##
## LEF for PtnCells ;
## created by Innovus v15.23-s045_1 on Sat Mar 22 13:16:31 2025
##

VERSION 5.8 ;

BUSBITCHARS "[]" ;
DIVIDERCHAR "/" ;

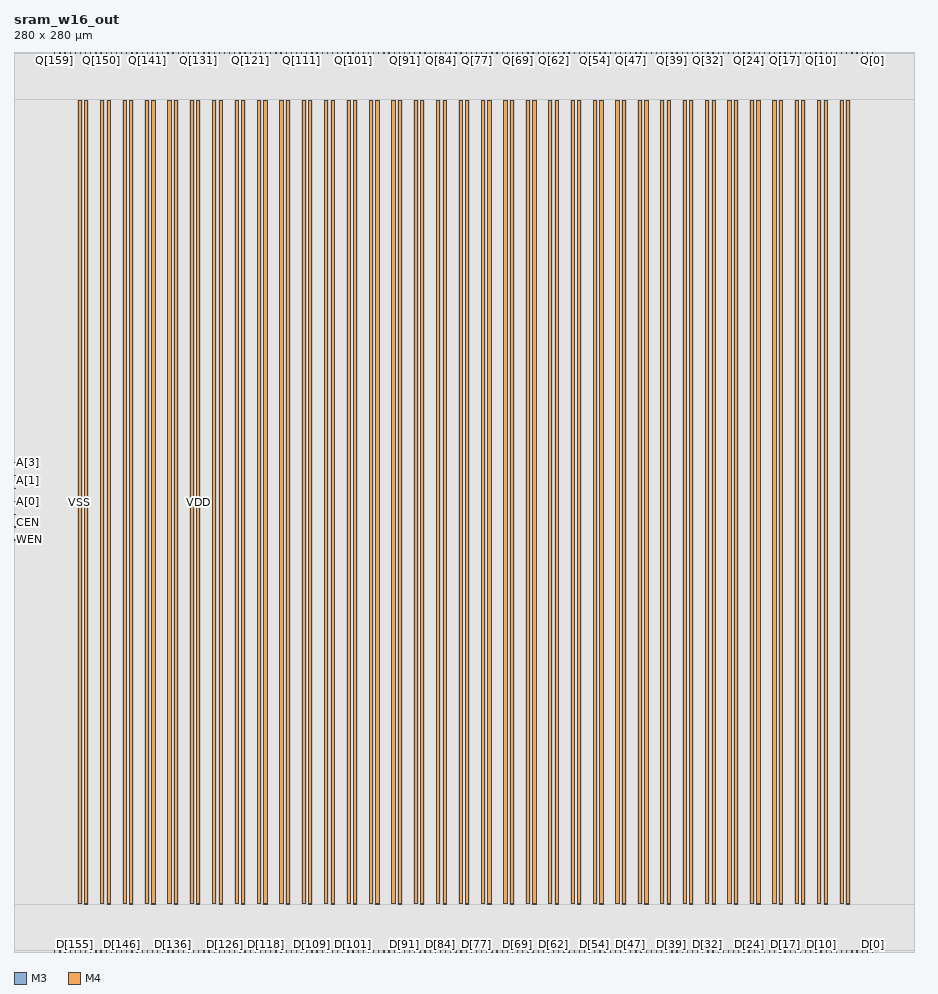
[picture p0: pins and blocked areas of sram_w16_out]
MACRO sram_w16_out
  CLASS BLOCK ;
  SIZE 280.0000 BY 280.0000 ;
  FOREIGN sram_w16_out 0.0000 0.0000 ;
  ORIGIN 0 0 ;
  SYMMETRY X Y R90 ;
  PIN clk
    DIRECTION INPUT ;
    USE SIGNAL ;
    PORT
      LAYER M3 ;
        RECT 0.0000 132.1500 0.5200 132.2500 ;
    END
  END clk
  PIN D[159]
    DIRECTION INPUT ;
    USE SIGNAL ;
    PORT
      LAYER M4 ;
        RECT 12.6500 0.0000 12.7500 0.5200 ;
    END
  END D[159]
  PIN D[158]
    DIRECTION INPUT ;
    USE SIGNAL ;
    PORT
      LAYER M4 ;
        RECT 14.2500 0.0000 14.3500 0.5200 ;
    END
  END D[158]
  PIN D[157]
    DIRECTION INPUT ;
    USE SIGNAL ;
    PORT
      LAYER M4 ;
        RECT 15.8500 0.0000 15.9500 0.5200 ;
    END
  END D[157]
  PIN D[156]
    DIRECTION INPUT ;
    USE SIGNAL ;
    PORT
      LAYER M4 ;
        RECT 17.4500 0.0000 17.5500 0.5200 ;
    END
  END D[156]
  PIN D[155]
    DIRECTION INPUT ;
    USE SIGNAL ;
    PORT
      LAYER M4 ;
        RECT 19.0500 0.0000 19.1500 0.5200 ;
    END
  END D[155]
  PIN D[154]
    DIRECTION INPUT ;
    USE SIGNAL ;
    PORT
      LAYER M4 ;
        RECT 20.6500 0.0000 20.7500 0.5200 ;
    END
  END D[154]
  PIN D[153]
    DIRECTION INPUT ;
    USE SIGNAL ;
    PORT
      LAYER M4 ;
        RECT 22.2500 0.0000 22.3500 0.5200 ;
    END
  END D[153]
  PIN D[152]
    DIRECTION INPUT ;
    USE SIGNAL ;
    PORT
      LAYER M4 ;
        RECT 23.8500 0.0000 23.9500 0.5200 ;
    END
  END D[152]
  PIN D[151]
    DIRECTION INPUT ;
    USE SIGNAL ;
    PORT
      LAYER M4 ;
        RECT 25.4500 0.0000 25.5500 0.5200 ;
    END
  END D[151]
  PIN D[150]
    DIRECTION INPUT ;
    USE SIGNAL ;
    PORT
      LAYER M4 ;
        RECT 27.0500 0.0000 27.1500 0.5200 ;
    END
  END D[150]
  PIN D[149]
    DIRECTION INPUT ;
    USE SIGNAL ;
    PORT
      LAYER M4 ;
        RECT 28.6500 0.0000 28.7500 0.5200 ;
    END
  END D[149]
  PIN D[148]
    DIRECTION INPUT ;
    USE SIGNAL ;
    PORT
      LAYER M4 ;
        RECT 30.2500 0.0000 30.3500 0.5200 ;
    END
  END D[148]
  PIN D[147]
    DIRECTION INPUT ;
    USE SIGNAL ;
    PORT
      LAYER M4 ;
        RECT 31.8500 0.0000 31.9500 0.5200 ;
    END
  END D[147]
  PIN D[146]
    DIRECTION INPUT ;
    USE SIGNAL ;
    PORT
      LAYER M4 ;
        RECT 33.4500 0.0000 33.5500 0.5200 ;
    END
  END D[146]
  PIN D[145]
    DIRECTION INPUT ;
    USE SIGNAL ;
    PORT
      LAYER M4 ;
        RECT 35.0500 0.0000 35.1500 0.5200 ;
    END
  END D[145]
  PIN D[144]
    DIRECTION INPUT ;
    USE SIGNAL ;
    PORT
      LAYER M4 ;
        RECT 36.6500 0.0000 36.7500 0.5200 ;
    END
  END D[144]
  PIN D[143]
    DIRECTION INPUT ;
    USE SIGNAL ;
    PORT
      LAYER M4 ;
        RECT 38.2500 0.0000 38.3500 0.5200 ;
    END
  END D[143]
  PIN D[142]
    DIRECTION INPUT ;
    USE SIGNAL ;
    PORT
      LAYER M4 ;
        RECT 39.8500 0.0000 39.9500 0.5200 ;
    END
  END D[142]
  PIN D[141]
    DIRECTION INPUT ;
    USE SIGNAL ;
    PORT
      LAYER M4 ;
        RECT 41.4500 0.0000 41.5500 0.5200 ;
    END
  END D[141]
  PIN D[140]
    DIRECTION INPUT ;
    USE SIGNAL ;
    PORT
      LAYER M4 ;
        RECT 43.0500 0.0000 43.1500 0.5200 ;
    END
  END D[140]
  PIN D[139]
    DIRECTION INPUT ;
    USE SIGNAL ;
    PORT
      LAYER M4 ;
        RECT 44.6500 0.0000 44.7500 0.5200 ;
    END
  END D[139]
  PIN D[138]
    DIRECTION INPUT ;
    USE SIGNAL ;
    PORT
      LAYER M4 ;
        RECT 46.2500 0.0000 46.3500 0.5200 ;
    END
  END D[138]
  PIN D[137]
    DIRECTION INPUT ;
    USE SIGNAL ;
    PORT
      LAYER M4 ;
        RECT 47.8500 0.0000 47.9500 0.5200 ;
    END
  END D[137]
  PIN D[136]
    DIRECTION INPUT ;
    USE SIGNAL ;
    PORT
      LAYER M4 ;
        RECT 49.4500 0.0000 49.5500 0.5200 ;
    END
  END D[136]
  PIN D[135]
    DIRECTION INPUT ;
    USE SIGNAL ;
    PORT
      LAYER M4 ;
        RECT 51.0500 0.0000 51.1500 0.5200 ;
    END
  END D[135]
  PIN D[134]
    DIRECTION INPUT ;
    USE SIGNAL ;
    PORT
      LAYER M4 ;
        RECT 52.6500 0.0000 52.7500 0.5200 ;
    END
  END D[134]
  PIN D[133]
    DIRECTION INPUT ;
    USE SIGNAL ;
    PORT
      LAYER M4 ;
        RECT 54.2500 0.0000 54.3500 0.5200 ;
    END
  END D[133]
  PIN D[132]
    DIRECTION INPUT ;
    USE SIGNAL ;
    PORT
      LAYER M4 ;
        RECT 55.8500 0.0000 55.9500 0.5200 ;
    END
  END D[132]
  PIN D[131]
    DIRECTION INPUT ;
    USE SIGNAL ;
    PORT
      LAYER M4 ;
        RECT 57.4500 0.0000 57.5500 0.5200 ;
    END
  END D[131]
  PIN D[130]
    DIRECTION INPUT ;
    USE SIGNAL ;
    PORT
      LAYER M4 ;
        RECT 59.0500 0.0000 59.1500 0.5200 ;
    END
  END D[130]
  PIN D[129]
    DIRECTION INPUT ;
    USE SIGNAL ;
    PORT
      LAYER M4 ;
        RECT 60.6500 0.0000 60.7500 0.5200 ;
    END
  END D[129]
  PIN D[128]
    DIRECTION INPUT ;
    USE SIGNAL ;
    PORT
      LAYER M4 ;
        RECT 62.2500 0.0000 62.3500 0.5200 ;
    END
  END D[128]
  PIN D[127]
    DIRECTION INPUT ;
    USE SIGNAL ;
    PORT
      LAYER M4 ;
        RECT 63.8500 0.0000 63.9500 0.5200 ;
    END
  END D[127]
  PIN D[126]
    DIRECTION INPUT ;
    USE SIGNAL ;
    PORT
      LAYER M4 ;
        RECT 65.4500 0.0000 65.5500 0.5200 ;
    END
  END D[126]
  PIN D[125]
    DIRECTION INPUT ;
    USE SIGNAL ;
    PORT
      LAYER M4 ;
        RECT 67.0500 0.0000 67.1500 0.5200 ;
    END
  END D[125]
  PIN D[124]
    DIRECTION INPUT ;
    USE SIGNAL ;
    PORT
      LAYER M4 ;
        RECT 68.6500 0.0000 68.7500 0.5200 ;
    END
  END D[124]
  PIN D[123]
    DIRECTION INPUT ;
    USE SIGNAL ;
    PORT
      LAYER M4 ;
        RECT 70.2500 0.0000 70.3500 0.5200 ;
    END
  END D[123]
  PIN D[122]
    DIRECTION INPUT ;
    USE SIGNAL ;
    PORT
      LAYER M4 ;
        RECT 71.8500 0.0000 71.9500 0.5200 ;
    END
  END D[122]
  PIN D[121]
    DIRECTION INPUT ;
    USE SIGNAL ;
    PORT
      LAYER M4 ;
        RECT 73.4500 0.0000 73.5500 0.5200 ;
    END
  END D[121]
  PIN D[120]
    DIRECTION INPUT ;
    USE SIGNAL ;
    PORT
      LAYER M4 ;
        RECT 75.0500 0.0000 75.1500 0.5200 ;
    END
  END D[120]
  PIN D[119]
    DIRECTION INPUT ;
    USE SIGNAL ;
    PORT
      LAYER M4 ;
        RECT 76.6500 0.0000 76.7500 0.5200 ;
    END
  END D[119]
  PIN D[118]
    DIRECTION INPUT ;
    USE SIGNAL ;
    PORT
      LAYER M4 ;
        RECT 78.2500 0.0000 78.3500 0.5200 ;
    END
  END D[118]
  PIN D[117]
    DIRECTION INPUT ;
    USE SIGNAL ;
    PORT
      LAYER M4 ;
        RECT 79.8500 0.0000 79.9500 0.5200 ;
    END
  END D[117]
  PIN D[116]
    DIRECTION INPUT ;
    USE SIGNAL ;
    PORT
      LAYER M4 ;
        RECT 81.4500 0.0000 81.5500 0.5200 ;
    END
  END D[116]
  PIN D[115]
    DIRECTION INPUT ;
    USE SIGNAL ;
    PORT
      LAYER M4 ;
        RECT 83.0500 0.0000 83.1500 0.5200 ;
    END
  END D[115]
  PIN D[114]
    DIRECTION INPUT ;
    USE SIGNAL ;
    PORT
      LAYER M4 ;
        RECT 84.6500 0.0000 84.7500 0.5200 ;
    END
  END D[114]
  PIN D[113]
    DIRECTION INPUT ;
    USE SIGNAL ;
    PORT
      LAYER M4 ;
        RECT 86.2500 0.0000 86.3500 0.5200 ;
    END
  END D[113]
  PIN D[112]
    DIRECTION INPUT ;
    USE SIGNAL ;
    PORT
      LAYER M4 ;
        RECT 87.8500 0.0000 87.9500 0.5200 ;
    END
  END D[112]
  PIN D[111]
    DIRECTION INPUT ;
    USE SIGNAL ;
    PORT
      LAYER M4 ;
        RECT 89.4500 0.0000 89.5500 0.5200 ;
    END
  END D[111]
  PIN D[110]
    DIRECTION INPUT ;
    USE SIGNAL ;
    PORT
      LAYER M4 ;
        RECT 91.0500 0.0000 91.1500 0.5200 ;
    END
  END D[110]
  PIN D[109]
    DIRECTION INPUT ;
    USE SIGNAL ;
    PORT
      LAYER M4 ;
        RECT 92.6500 0.0000 92.7500 0.5200 ;
    END
  END D[109]
  PIN D[108]
    DIRECTION INPUT ;
    USE SIGNAL ;
    PORT
      LAYER M4 ;
        RECT 94.2500 0.0000 94.3500 0.5200 ;
    END
  END D[108]
  PIN D[107]
    DIRECTION INPUT ;
    USE SIGNAL ;
    PORT
      LAYER M4 ;
        RECT 95.8500 0.0000 95.9500 0.5200 ;
    END
  END D[107]
  PIN D[106]
    DIRECTION INPUT ;
    USE SIGNAL ;
    PORT
      LAYER M4 ;
        RECT 97.4500 0.0000 97.5500 0.5200 ;
    END
  END D[106]
  PIN D[105]
    DIRECTION INPUT ;
    USE SIGNAL ;
    PORT
      LAYER M4 ;
        RECT 99.0500 0.0000 99.1500 0.5200 ;
    END
  END D[105]
  PIN D[104]
    DIRECTION INPUT ;
    USE SIGNAL ;
    PORT
      LAYER M4 ;
        RECT 100.6500 0.0000 100.7500 0.5200 ;
    END
  END D[104]
  PIN D[103]
    DIRECTION INPUT ;
    USE SIGNAL ;
    PORT
      LAYER M4 ;
        RECT 102.2500 0.0000 102.3500 0.5200 ;
    END
  END D[103]
  PIN D[102]
    DIRECTION INPUT ;
    USE SIGNAL ;
    PORT
      LAYER M4 ;
        RECT 103.8500 0.0000 103.9500 0.5200 ;
    END
  END D[102]
  PIN D[101]
    DIRECTION INPUT ;
    USE SIGNAL ;
    PORT
      LAYER M4 ;
        RECT 105.4500 0.0000 105.5500 0.5200 ;
    END
  END D[101]
  PIN D[100]
    DIRECTION INPUT ;
    USE SIGNAL ;
    PORT
      LAYER M4 ;
        RECT 107.0500 0.0000 107.1500 0.5200 ;
    END
  END D[100]
  PIN D[99]
    DIRECTION INPUT ;
    USE SIGNAL ;
    PORT
      LAYER M4 ;
        RECT 108.6500 0.0000 108.7500 0.5200 ;
    END
  END D[99]
  PIN D[98]
    DIRECTION INPUT ;
    USE SIGNAL ;
    PORT
      LAYER M4 ;
        RECT 110.2500 0.0000 110.3500 0.5200 ;
    END
  END D[98]
  PIN D[97]
    DIRECTION INPUT ;
    USE SIGNAL ;
    PORT
      LAYER M4 ;
        RECT 111.8500 0.0000 111.9500 0.5200 ;
    END
  END D[97]
  PIN D[96]
    DIRECTION INPUT ;
    USE SIGNAL ;
    PORT
      LAYER M4 ;
        RECT 113.4500 0.0000 113.5500 0.5200 ;
    END
  END D[96]
  PIN D[95]
    DIRECTION INPUT ;
    USE SIGNAL ;
    PORT
      LAYER M4 ;
        RECT 115.0500 0.0000 115.1500 0.5200 ;
    END
  END D[95]
  PIN D[94]
    DIRECTION INPUT ;
    USE SIGNAL ;
    PORT
      LAYER M4 ;
        RECT 116.6500 0.0000 116.7500 0.5200 ;
    END
  END D[94]
  PIN D[93]
    DIRECTION INPUT ;
    USE SIGNAL ;
    PORT
      LAYER M4 ;
        RECT 118.2500 0.0000 118.3500 0.5200 ;
    END
  END D[93]
  PIN D[92]
    DIRECTION INPUT ;
    USE SIGNAL ;
    PORT
      LAYER M4 ;
        RECT 119.8500 0.0000 119.9500 0.5200 ;
    END
  END D[92]
  PIN D[91]
    DIRECTION INPUT ;
    USE SIGNAL ;
    PORT
      LAYER M4 ;
        RECT 121.4500 0.0000 121.5500 0.5200 ;
    END
  END D[91]
  PIN D[90]
    DIRECTION INPUT ;
    USE SIGNAL ;
    PORT
      LAYER M4 ;
        RECT 123.0500 0.0000 123.1500 0.5200 ;
    END
  END D[90]
  PIN D[89]
    DIRECTION INPUT ;
    USE SIGNAL ;
    PORT
      LAYER M4 ;
        RECT 124.6500 0.0000 124.7500 0.5200 ;
    END
  END D[89]
  PIN D[88]
    DIRECTION INPUT ;
    USE SIGNAL ;
    PORT
      LAYER M4 ;
        RECT 126.2500 0.0000 126.3500 0.5200 ;
    END
  END D[88]
  PIN D[87]
    DIRECTION INPUT ;
    USE SIGNAL ;
    PORT
      LAYER M4 ;
        RECT 127.8500 0.0000 127.9500 0.5200 ;
    END
  END D[87]
  PIN D[86]
    DIRECTION INPUT ;
    USE SIGNAL ;
    PORT
      LAYER M4 ;
        RECT 129.4500 0.0000 129.5500 0.5200 ;
    END
  END D[86]
  PIN D[85]
    DIRECTION INPUT ;
    USE SIGNAL ;
    PORT
      LAYER M4 ;
        RECT 131.0500 0.0000 131.1500 0.5200 ;
    END
  END D[85]
  PIN D[84]
    DIRECTION INPUT ;
    USE SIGNAL ;
    PORT
      LAYER M4 ;
        RECT 132.6500 0.0000 132.7500 0.5200 ;
    END
  END D[84]
  PIN D[83]
    DIRECTION INPUT ;
    USE SIGNAL ;
    PORT
      LAYER M4 ;
        RECT 134.2500 0.0000 134.3500 0.5200 ;
    END
  END D[83]
  PIN D[82]
    DIRECTION INPUT ;
    USE SIGNAL ;
    PORT
      LAYER M4 ;
        RECT 135.8500 0.0000 135.9500 0.5200 ;
    END
  END D[82]
  PIN D[81]
    DIRECTION INPUT ;
    USE SIGNAL ;
    PORT
      LAYER M4 ;
        RECT 137.4500 0.0000 137.5500 0.5200 ;
    END
  END D[81]
  PIN D[80]
    DIRECTION INPUT ;
    USE SIGNAL ;
    PORT
      LAYER M4 ;
        RECT 139.0500 0.0000 139.1500 0.5200 ;
    END
  END D[80]
  PIN D[79]
    DIRECTION INPUT ;
    USE SIGNAL ;
    PORT
      LAYER M4 ;
        RECT 140.6500 0.0000 140.7500 0.5200 ;
    END
  END D[79]
  PIN D[78]
    DIRECTION INPUT ;
    USE SIGNAL ;
    PORT
      LAYER M4 ;
        RECT 142.2500 0.0000 142.3500 0.5200 ;
    END
  END D[78]
  PIN D[77]
    DIRECTION INPUT ;
    USE SIGNAL ;
    PORT
      LAYER M4 ;
        RECT 143.8500 0.0000 143.9500 0.5200 ;
    END
  END D[77]
  PIN D[76]
    DIRECTION INPUT ;
    USE SIGNAL ;
    PORT
      LAYER M4 ;
        RECT 145.4500 0.0000 145.5500 0.5200 ;
    END
  END D[76]
  PIN D[75]
    DIRECTION INPUT ;
    USE SIGNAL ;
    PORT
      LAYER M4 ;
        RECT 147.0500 0.0000 147.1500 0.5200 ;
    END
  END D[75]
  PIN D[74]
    DIRECTION INPUT ;
    USE SIGNAL ;
    PORT
      LAYER M4 ;
        RECT 148.6500 0.0000 148.7500 0.5200 ;
    END
  END D[74]
  PIN D[73]
    DIRECTION INPUT ;
    USE SIGNAL ;
    PORT
      LAYER M4 ;
        RECT 150.2500 0.0000 150.3500 0.5200 ;
    END
  END D[73]
  PIN D[72]
    DIRECTION INPUT ;
    USE SIGNAL ;
    PORT
      LAYER M4 ;
        RECT 151.8500 0.0000 151.9500 0.5200 ;
    END
  END D[72]
  PIN D[71]
    DIRECTION INPUT ;
    USE SIGNAL ;
    PORT
      LAYER M4 ;
        RECT 153.4500 0.0000 153.5500 0.5200 ;
    END
  END D[71]
  PIN D[70]
    DIRECTION INPUT ;
    USE SIGNAL ;
    PORT
      LAYER M4 ;
        RECT 155.0500 0.0000 155.1500 0.5200 ;
    END
  END D[70]
  PIN D[69]
    DIRECTION INPUT ;
    USE SIGNAL ;
    PORT
      LAYER M4 ;
        RECT 156.6500 0.0000 156.7500 0.5200 ;
    END
  END D[69]
  PIN D[68]
    DIRECTION INPUT ;
    USE SIGNAL ;
    PORT
      LAYER M4 ;
        RECT 158.2500 0.0000 158.3500 0.5200 ;
    END
  END D[68]
  PIN D[67]
    DIRECTION INPUT ;
    USE SIGNAL ;
    PORT
      LAYER M4 ;
        RECT 159.8500 0.0000 159.9500 0.5200 ;
    END
  END D[67]
  PIN D[66]
    DIRECTION INPUT ;
    USE SIGNAL ;
    PORT
      LAYER M4 ;
        RECT 161.4500 0.0000 161.5500 0.5200 ;
    END
  END D[66]
  PIN D[65]
    DIRECTION INPUT ;
    USE SIGNAL ;
    PORT
      LAYER M4 ;
        RECT 163.0500 0.0000 163.1500 0.5200 ;
    END
  END D[65]
  PIN D[64]
    DIRECTION INPUT ;
    USE SIGNAL ;
    PORT
      LAYER M4 ;
        RECT 164.6500 0.0000 164.7500 0.5200 ;
    END
  END D[64]
  PIN D[63]
    DIRECTION INPUT ;
    USE SIGNAL ;
    PORT
      LAYER M4 ;
        RECT 166.2500 0.0000 166.3500 0.5200 ;
    END
  END D[63]
  PIN D[62]
    DIRECTION INPUT ;
    USE SIGNAL ;
    PORT
      LAYER M4 ;
        RECT 167.8500 0.0000 167.9500 0.5200 ;
    END
  END D[62]
  PIN D[61]
    DIRECTION INPUT ;
    USE SIGNAL ;
    PORT
      LAYER M4 ;
        RECT 169.4500 0.0000 169.5500 0.5200 ;
    END
  END D[61]
  PIN D[60]
    DIRECTION INPUT ;
    USE SIGNAL ;
    PORT
      LAYER M4 ;
        RECT 171.0500 0.0000 171.1500 0.5200 ;
    END
  END D[60]
  PIN D[59]
    DIRECTION INPUT ;
    USE SIGNAL ;
    PORT
      LAYER M4 ;
        RECT 172.6500 0.0000 172.7500 0.5200 ;
    END
  END D[59]
  PIN D[58]
    DIRECTION INPUT ;
    USE SIGNAL ;
    PORT
      LAYER M4 ;
        RECT 174.2500 0.0000 174.3500 0.5200 ;
    END
  END D[58]
  PIN D[57]
    DIRECTION INPUT ;
    USE SIGNAL ;
    PORT
      LAYER M4 ;
        RECT 175.8500 0.0000 175.9500 0.5200 ;
    END
  END D[57]
  PIN D[56]
    DIRECTION INPUT ;
    USE SIGNAL ;
    PORT
      LAYER M4 ;
        RECT 177.4500 0.0000 177.5500 0.5200 ;
    END
  END D[56]
  PIN D[55]
    DIRECTION INPUT ;
    USE SIGNAL ;
    PORT
      LAYER M4 ;
        RECT 179.0500 0.0000 179.1500 0.5200 ;
    END
  END D[55]
  PIN D[54]
    DIRECTION INPUT ;
    USE SIGNAL ;
    PORT
      LAYER M4 ;
        RECT 180.6500 0.0000 180.7500 0.5200 ;
    END
  END D[54]
  PIN D[53]
    DIRECTION INPUT ;
    USE SIGNAL ;
    PORT
      LAYER M4 ;
        RECT 182.2500 0.0000 182.3500 0.5200 ;
    END
  END D[53]
  PIN D[52]
    DIRECTION INPUT ;
    USE SIGNAL ;
    PORT
      LAYER M4 ;
        RECT 183.8500 0.0000 183.9500 0.5200 ;
    END
  END D[52]
  PIN D[51]
    DIRECTION INPUT ;
    USE SIGNAL ;
    PORT
      LAYER M4 ;
        RECT 185.4500 0.0000 185.5500 0.5200 ;
    END
  END D[51]
  PIN D[50]
    DIRECTION INPUT ;
    USE SIGNAL ;
    PORT
      LAYER M4 ;
        RECT 187.0500 0.0000 187.1500 0.5200 ;
    END
  END D[50]
  PIN D[49]
    DIRECTION INPUT ;
    USE SIGNAL ;
    PORT
      LAYER M4 ;
        RECT 188.6500 0.0000 188.7500 0.5200 ;
    END
  END D[49]
  PIN D[48]
    DIRECTION INPUT ;
    USE SIGNAL ;
    PORT
      LAYER M4 ;
        RECT 190.2500 0.0000 190.3500 0.5200 ;
    END
  END D[48]
  PIN D[47]
    DIRECTION INPUT ;
    USE SIGNAL ;
    PORT
      LAYER M4 ;
        RECT 191.8500 0.0000 191.9500 0.5200 ;
    END
  END D[47]
  PIN D[46]
    DIRECTION INPUT ;
    USE SIGNAL ;
    PORT
      LAYER M4 ;
        RECT 193.4500 0.0000 193.5500 0.5200 ;
    END
  END D[46]
  PIN D[45]
    DIRECTION INPUT ;
    USE SIGNAL ;
    PORT
      LAYER M4 ;
        RECT 195.0500 0.0000 195.1500 0.5200 ;
    END
  END D[45]
  PIN D[44]
    DIRECTION INPUT ;
    USE SIGNAL ;
    PORT
      LAYER M4 ;
        RECT 196.6500 0.0000 196.7500 0.5200 ;
    END
  END D[44]
  PIN D[43]
    DIRECTION INPUT ;
    USE SIGNAL ;
    PORT
      LAYER M4 ;
        RECT 198.2500 0.0000 198.3500 0.5200 ;
    END
  END D[43]
  PIN D[42]
    DIRECTION INPUT ;
    USE SIGNAL ;
    PORT
      LAYER M4 ;
        RECT 199.8500 0.0000 199.9500 0.5200 ;
    END
  END D[42]
  PIN D[41]
    DIRECTION INPUT ;
    USE SIGNAL ;
    PORT
      LAYER M4 ;
        RECT 201.4500 0.0000 201.5500 0.5200 ;
    END
  END D[41]
  PIN D[40]
    DIRECTION INPUT ;
    USE SIGNAL ;
    PORT
      LAYER M4 ;
        RECT 203.0500 0.0000 203.1500 0.5200 ;
    END
  END D[40]
  PIN D[39]
    DIRECTION INPUT ;
    USE SIGNAL ;
    PORT
      LAYER M4 ;
        RECT 204.6500 0.0000 204.7500 0.5200 ;
    END
  END D[39]
  PIN D[38]
    DIRECTION INPUT ;
    USE SIGNAL ;
    PORT
      LAYER M4 ;
        RECT 206.2500 0.0000 206.3500 0.5200 ;
    END
  END D[38]
  PIN D[37]
    DIRECTION INPUT ;
    USE SIGNAL ;
    PORT
      LAYER M4 ;
        RECT 207.8500 0.0000 207.9500 0.5200 ;
    END
  END D[37]
  PIN D[36]
    DIRECTION INPUT ;
    USE SIGNAL ;
    PORT
      LAYER M4 ;
        RECT 209.4500 0.0000 209.5500 0.5200 ;
    END
  END D[36]
  PIN D[35]
    DIRECTION INPUT ;
    USE SIGNAL ;
    PORT
      LAYER M4 ;
        RECT 211.0500 0.0000 211.1500 0.5200 ;
    END
  END D[35]
  PIN D[34]
    DIRECTION INPUT ;
    USE SIGNAL ;
    PORT
      LAYER M4 ;
        RECT 212.6500 0.0000 212.7500 0.5200 ;
    END
  END D[34]
  PIN D[33]
    DIRECTION INPUT ;
    USE SIGNAL ;
    PORT
      LAYER M4 ;
        RECT 214.2500 0.0000 214.3500 0.5200 ;
    END
  END D[33]
  PIN D[32]
    DIRECTION INPUT ;
    USE SIGNAL ;
    PORT
      LAYER M4 ;
        RECT 215.8500 0.0000 215.9500 0.5200 ;
    END
  END D[32]
  PIN D[31]
    DIRECTION INPUT ;
    USE SIGNAL ;
    PORT
      LAYER M4 ;
        RECT 217.4500 0.0000 217.5500 0.5200 ;
    END
  END D[31]
  PIN D[30]
    DIRECTION INPUT ;
    USE SIGNAL ;
    PORT
      LAYER M4 ;
        RECT 219.0500 0.0000 219.1500 0.5200 ;
    END
  END D[30]
  PIN D[29]
    DIRECTION INPUT ;
    USE SIGNAL ;
    PORT
      LAYER M4 ;
        RECT 220.6500 0.0000 220.7500 0.5200 ;
    END
  END D[29]
  PIN D[28]
    DIRECTION INPUT ;
    USE SIGNAL ;
    PORT
      LAYER M4 ;
        RECT 222.2500 0.0000 222.3500 0.5200 ;
    END
  END D[28]
  PIN D[27]
    DIRECTION INPUT ;
    USE SIGNAL ;
    PORT
      LAYER M4 ;
        RECT 223.8500 0.0000 223.9500 0.5200 ;
    END
  END D[27]
  PIN D[26]
    DIRECTION INPUT ;
    USE SIGNAL ;
    PORT
      LAYER M4 ;
        RECT 225.4500 0.0000 225.5500 0.5200 ;
    END
  END D[26]
  PIN D[25]
    DIRECTION INPUT ;
    USE SIGNAL ;
    PORT
      LAYER M4 ;
        RECT 227.0500 0.0000 227.1500 0.5200 ;
    END
  END D[25]
  PIN D[24]
    DIRECTION INPUT ;
    USE SIGNAL ;
    PORT
      LAYER M4 ;
        RECT 228.6500 0.0000 228.7500 0.5200 ;
    END
  END D[24]
  PIN D[23]
    DIRECTION INPUT ;
    USE SIGNAL ;
    PORT
      LAYER M4 ;
        RECT 230.2500 0.0000 230.3500 0.5200 ;
    END
  END D[23]
  PIN D[22]
    DIRECTION INPUT ;
    USE SIGNAL ;
    PORT
      LAYER M4 ;
        RECT 231.8500 0.0000 231.9500 0.5200 ;
    END
  END D[22]
  PIN D[21]
    DIRECTION INPUT ;
    USE SIGNAL ;
    PORT
      LAYER M4 ;
        RECT 233.4500 0.0000 233.5500 0.5200 ;
    END
  END D[21]
  PIN D[20]
    DIRECTION INPUT ;
    USE SIGNAL ;
    PORT
      LAYER M4 ;
        RECT 235.0500 0.0000 235.1500 0.5200 ;
    END
  END D[20]
  PIN D[19]
    DIRECTION INPUT ;
    USE SIGNAL ;
    PORT
      LAYER M4 ;
        RECT 236.6500 0.0000 236.7500 0.5200 ;
    END
  END D[19]
  PIN D[18]
    DIRECTION INPUT ;
    USE SIGNAL ;
    PORT
      LAYER M4 ;
        RECT 238.2500 0.0000 238.3500 0.5200 ;
    END
  END D[18]
  PIN D[17]
    DIRECTION INPUT ;
    USE SIGNAL ;
    PORT
      LAYER M4 ;
        RECT 239.8500 0.0000 239.9500 0.5200 ;
    END
  END D[17]
  PIN D[16]
    DIRECTION INPUT ;
    USE SIGNAL ;
    PORT
      LAYER M4 ;
        RECT 241.4500 0.0000 241.5500 0.5200 ;
    END
  END D[16]
  PIN D[15]
    DIRECTION INPUT ;
    USE SIGNAL ;
    PORT
      LAYER M4 ;
        RECT 243.0500 0.0000 243.1500 0.5200 ;
    END
  END D[15]
  PIN D[14]
    DIRECTION INPUT ;
    USE SIGNAL ;
    PORT
      LAYER M4 ;
        RECT 244.6500 0.0000 244.7500 0.5200 ;
    END
  END D[14]
  PIN D[13]
    DIRECTION INPUT ;
    USE SIGNAL ;
    PORT
      LAYER M4 ;
        RECT 246.2500 0.0000 246.3500 0.5200 ;
    END
  END D[13]
  PIN D[12]
    DIRECTION INPUT ;
    USE SIGNAL ;
    PORT
      LAYER M4 ;
        RECT 247.8500 0.0000 247.9500 0.5200 ;
    END
  END D[12]
  PIN D[11]
    DIRECTION INPUT ;
    USE SIGNAL ;
    PORT
      LAYER M4 ;
        RECT 249.4500 0.0000 249.5500 0.5200 ;
    END
  END D[11]
  PIN D[10]
    DIRECTION INPUT ;
    USE SIGNAL ;
    PORT
      LAYER M4 ;
        RECT 251.0500 0.0000 251.1500 0.5200 ;
    END
  END D[10]
  PIN D[9]
    DIRECTION INPUT ;
    USE SIGNAL ;
    PORT
      LAYER M4 ;
        RECT 252.6500 0.0000 252.7500 0.5200 ;
    END
  END D[9]
  PIN D[8]
    DIRECTION INPUT ;
    USE SIGNAL ;
    PORT
      LAYER M4 ;
        RECT 254.2500 0.0000 254.3500 0.5200 ;
    END
  END D[8]
  PIN D[7]
    DIRECTION INPUT ;
    USE SIGNAL ;
    PORT
      LAYER M4 ;
        RECT 255.8500 0.0000 255.9500 0.5200 ;
    END
  END D[7]
  PIN D[6]
    DIRECTION INPUT ;
    USE SIGNAL ;
    PORT
      LAYER M4 ;
        RECT 257.4500 0.0000 257.5500 0.5200 ;
    END
  END D[6]
  PIN D[5]
    DIRECTION INPUT ;
    USE SIGNAL ;
    PORT
      LAYER M4 ;
        RECT 259.0500 0.0000 259.1500 0.5200 ;
    END
  END D[5]
  PIN D[4]
    DIRECTION INPUT ;
    USE SIGNAL ;
    PORT
      LAYER M4 ;
        RECT 260.6500 0.0000 260.7500 0.5200 ;
    END
  END D[4]
  PIN D[3]
    DIRECTION INPUT ;
    USE SIGNAL ;
    PORT
      LAYER M4 ;
        RECT 262.2500 0.0000 262.3500 0.5200 ;
    END
  END D[3]
  PIN D[2]
    DIRECTION INPUT ;
    USE SIGNAL ;
    PORT
      LAYER M4 ;
        RECT 263.8500 0.0000 263.9500 0.5200 ;
    END
  END D[2]
  PIN D[1]
    DIRECTION INPUT ;
    USE SIGNAL ;
    PORT
      LAYER M4 ;
        RECT 265.4500 0.0000 265.5500 0.5200 ;
    END
  END D[1]
  PIN D[0]
    DIRECTION INPUT ;
    USE SIGNAL ;
    PORT
      LAYER M4 ;
        RECT 267.0500 0.0000 267.1500 0.5200 ;
    END
  END D[0]
  PIN Q[159]
    DIRECTION OUTPUT ;
    USE SIGNAL ;
    PORT
      LAYER M4 ;
        RECT 12.6500 279.4800 12.7500 280.0000 ;
    END
  END Q[159]
  PIN Q[158]
    DIRECTION OUTPUT ;
    USE SIGNAL ;
    PORT
      LAYER M4 ;
        RECT 14.2500 279.4800 14.3500 280.0000 ;
    END
  END Q[158]
  PIN Q[157]
    DIRECTION OUTPUT ;
    USE SIGNAL ;
    PORT
      LAYER M4 ;
        RECT 15.8500 279.4800 15.9500 280.0000 ;
    END
  END Q[157]
  PIN Q[156]
    DIRECTION OUTPUT ;
    USE SIGNAL ;
    PORT
      LAYER M4 ;
        RECT 17.4500 279.4800 17.5500 280.0000 ;
    END
  END Q[156]
  PIN Q[155]
    DIRECTION OUTPUT ;
    USE SIGNAL ;
    PORT
      LAYER M4 ;
        RECT 19.0500 279.4800 19.1500 280.0000 ;
    END
  END Q[155]
  PIN Q[154]
    DIRECTION OUTPUT ;
    USE SIGNAL ;
    PORT
      LAYER M4 ;
        RECT 20.6500 279.4800 20.7500 280.0000 ;
    END
  END Q[154]
  PIN Q[153]
    DIRECTION OUTPUT ;
    USE SIGNAL ;
    PORT
      LAYER M4 ;
        RECT 22.2500 279.4800 22.3500 280.0000 ;
    END
  END Q[153]
  PIN Q[152]
    DIRECTION OUTPUT ;
    USE SIGNAL ;
    PORT
      LAYER M4 ;
        RECT 23.8500 279.4800 23.9500 280.0000 ;
    END
  END Q[152]
  PIN Q[151]
    DIRECTION OUTPUT ;
    USE SIGNAL ;
    PORT
      LAYER M4 ;
        RECT 25.4500 279.4800 25.5500 280.0000 ;
    END
  END Q[151]
  PIN Q[150]
    DIRECTION OUTPUT ;
    USE SIGNAL ;
    PORT
      LAYER M4 ;
        RECT 27.0500 279.4800 27.1500 280.0000 ;
    END
  END Q[150]
  PIN Q[149]
    DIRECTION OUTPUT ;
    USE SIGNAL ;
    PORT
      LAYER M4 ;
        RECT 28.6500 279.4800 28.7500 280.0000 ;
    END
  END Q[149]
  PIN Q[148]
    DIRECTION OUTPUT ;
    USE SIGNAL ;
    PORT
      LAYER M4 ;
        RECT 30.2500 279.4800 30.3500 280.0000 ;
    END
  END Q[148]
  PIN Q[147]
    DIRECTION OUTPUT ;
    USE SIGNAL ;
    PORT
      LAYER M4 ;
        RECT 31.8500 279.4800 31.9500 280.0000 ;
    END
  END Q[147]
  PIN Q[146]
    DIRECTION OUTPUT ;
    USE SIGNAL ;
    PORT
      LAYER M4 ;
        RECT 33.4500 279.4800 33.5500 280.0000 ;
    END
  END Q[146]
  PIN Q[145]
    DIRECTION OUTPUT ;
    USE SIGNAL ;
    PORT
      LAYER M4 ;
        RECT 35.0500 279.4800 35.1500 280.0000 ;
    END
  END Q[145]
  PIN Q[144]
    DIRECTION OUTPUT ;
    USE SIGNAL ;
    PORT
      LAYER M4 ;
        RECT 36.6500 279.4800 36.7500 280.0000 ;
    END
  END Q[144]
  PIN Q[143]
    DIRECTION OUTPUT ;
    USE SIGNAL ;
    PORT
      LAYER M4 ;
        RECT 38.2500 279.4800 38.3500 280.0000 ;
    END
  END Q[143]
  PIN Q[142]
    DIRECTION OUTPUT ;
    USE SIGNAL ;
    PORT
      LAYER M4 ;
        RECT 39.8500 279.4800 39.9500 280.0000 ;
    END
  END Q[142]
  PIN Q[141]
    DIRECTION OUTPUT ;
    USE SIGNAL ;
    PORT
      LAYER M4 ;
        RECT 41.4500 279.4800 41.5500 280.0000 ;
    END
  END Q[141]
  PIN Q[140]
    DIRECTION OUTPUT ;
    USE SIGNAL ;
    PORT
      LAYER M4 ;
        RECT 43.0500 279.4800 43.1500 280.0000 ;
    END
  END Q[140]
  PIN Q[139]
    DIRECTION OUTPUT ;
    USE SIGNAL ;
    PORT
      LAYER M4 ;
        RECT 44.6500 279.4800 44.7500 280.0000 ;
    END
  END Q[139]
  PIN Q[138]
    DIRECTION OUTPUT ;
    USE SIGNAL ;
    PORT
      LAYER M4 ;
        RECT 46.2500 279.4800 46.3500 280.0000 ;
    END
  END Q[138]
  PIN Q[137]
    DIRECTION OUTPUT ;
    USE SIGNAL ;
    PORT
      LAYER M4 ;
        RECT 47.8500 279.4800 47.9500 280.0000 ;
    END
  END Q[137]
  PIN Q[136]
    DIRECTION OUTPUT ;
    USE SIGNAL ;
    PORT
      LAYER M4 ;
        RECT 49.4500 279.4800 49.5500 280.0000 ;
    END
  END Q[136]
  PIN Q[135]
    DIRECTION OUTPUT ;
    USE SIGNAL ;
    PORT
      LAYER M4 ;
        RECT 51.0500 279.4800 51.1500 280.0000 ;
    END
  END Q[135]
  PIN Q[134]
    DIRECTION OUTPUT ;
    USE SIGNAL ;
    PORT
      LAYER M4 ;
        RECT 52.6500 279.4800 52.7500 280.0000 ;
    END
  END Q[134]
  PIN Q[133]
    DIRECTION OUTPUT ;
    USE SIGNAL ;
    PORT
      LAYER M4 ;
        RECT 54.2500 279.4800 54.3500 280.0000 ;
    END
  END Q[133]
  PIN Q[132]
    DIRECTION OUTPUT ;
    USE SIGNAL ;
    PORT
      LAYER M4 ;
        RECT 55.8500 279.4800 55.9500 280.0000 ;
    END
  END Q[132]
  PIN Q[131]
    DIRECTION OUTPUT ;
    USE SIGNAL ;
    PORT
      LAYER M4 ;
        RECT 57.4500 279.4800 57.5500 280.0000 ;
    END
  END Q[131]
  PIN Q[130]
    DIRECTION OUTPUT ;
    USE SIGNAL ;
    PORT
      LAYER M4 ;
        RECT 59.0500 279.4800 59.1500 280.0000 ;
    END
  END Q[130]
  PIN Q[129]
    DIRECTION OUTPUT ;
    USE SIGNAL ;
    PORT
      LAYER M4 ;
        RECT 60.6500 279.4800 60.7500 280.0000 ;
    END
  END Q[129]
  PIN Q[128]
    DIRECTION OUTPUT ;
    USE SIGNAL ;
    PORT
      LAYER M4 ;
        RECT 62.2500 279.4800 62.3500 280.0000 ;
    END
  END Q[128]
  PIN Q[127]
    DIRECTION OUTPUT ;
    USE SIGNAL ;
    PORT
      LAYER M4 ;
        RECT 63.8500 279.4800 63.9500 280.0000 ;
    END
  END Q[127]
  PIN Q[126]
    DIRECTION OUTPUT ;
    USE SIGNAL ;
    PORT
      LAYER M4 ;
        RECT 65.4500 279.4800 65.5500 280.0000 ;
    END
  END Q[126]
  PIN Q[125]
    DIRECTION OUTPUT ;
    USE SIGNAL ;
    PORT
      LAYER M4 ;
        RECT 67.0500 279.4800 67.1500 280.0000 ;
    END
  END Q[125]
  PIN Q[124]
    DIRECTION OUTPUT ;
    USE SIGNAL ;
    PORT
      LAYER M4 ;
        RECT 68.6500 279.4800 68.7500 280.0000 ;
    END
  END Q[124]
  PIN Q[123]
    DIRECTION OUTPUT ;
    USE SIGNAL ;
    PORT
      LAYER M4 ;
        RECT 70.2500 279.4800 70.3500 280.0000 ;
    END
  END Q[123]
  PIN Q[122]
    DIRECTION OUTPUT ;
    USE SIGNAL ;
    PORT
      LAYER M4 ;
        RECT 71.8500 279.4800 71.9500 280.0000 ;
    END
  END Q[122]
  PIN Q[121]
    DIRECTION OUTPUT ;
    USE SIGNAL ;
    PORT
      LAYER M4 ;
        RECT 73.4500 279.4800 73.5500 280.0000 ;
    END
  END Q[121]
  PIN Q[120]
    DIRECTION OUTPUT ;
    USE SIGNAL ;
    PORT
      LAYER M4 ;
        RECT 75.0500 279.4800 75.1500 280.0000 ;
    END
  END Q[120]
  PIN Q[119]
    DIRECTION OUTPUT ;
    USE SIGNAL ;
    PORT
      LAYER M4 ;
        RECT 76.6500 279.4800 76.7500 280.0000 ;
    END
  END Q[119]
  PIN Q[118]
    DIRECTION OUTPUT ;
    USE SIGNAL ;
    PORT
      LAYER M4 ;
        RECT 78.2500 279.4800 78.3500 280.0000 ;
    END
  END Q[118]
  PIN Q[117]
    DIRECTION OUTPUT ;
    USE SIGNAL ;
    PORT
      LAYER M4 ;
        RECT 79.8500 279.4800 79.9500 280.0000 ;
    END
  END Q[117]
  PIN Q[116]
    DIRECTION OUTPUT ;
    USE SIGNAL ;
    PORT
      LAYER M4 ;
        RECT 81.4500 279.4800 81.5500 280.0000 ;
    END
  END Q[116]
  PIN Q[115]
    DIRECTION OUTPUT ;
    USE SIGNAL ;
    PORT
      LAYER M4 ;
        RECT 83.0500 279.4800 83.1500 280.0000 ;
    END
  END Q[115]
  PIN Q[114]
    DIRECTION OUTPUT ;
    USE SIGNAL ;
    PORT
      LAYER M4 ;
        RECT 84.6500 279.4800 84.7500 280.0000 ;
    END
  END Q[114]
  PIN Q[113]
    DIRECTION OUTPUT ;
    USE SIGNAL ;
    PORT
      LAYER M4 ;
        RECT 86.2500 279.4800 86.3500 280.0000 ;
    END
  END Q[113]
  PIN Q[112]
    DIRECTION OUTPUT ;
    USE SIGNAL ;
    PORT
      LAYER M4 ;
        RECT 87.8500 279.4800 87.9500 280.0000 ;
    END
  END Q[112]
  PIN Q[111]
    DIRECTION OUTPUT ;
    USE SIGNAL ;
    PORT
      LAYER M4 ;
        RECT 89.4500 279.4800 89.5500 280.0000 ;
    END
  END Q[111]
  PIN Q[110]
    DIRECTION OUTPUT ;
    USE SIGNAL ;
    PORT
      LAYER M4 ;
        RECT 91.0500 279.4800 91.1500 280.0000 ;
    END
  END Q[110]
  PIN Q[109]
    DIRECTION OUTPUT ;
    USE SIGNAL ;
    PORT
      LAYER M4 ;
        RECT 92.6500 279.4800 92.7500 280.0000 ;
    END
  END Q[109]
  PIN Q[108]
    DIRECTION OUTPUT ;
    USE SIGNAL ;
    PORT
      LAYER M4 ;
        RECT 94.2500 279.4800 94.3500 280.0000 ;
    END
  END Q[108]
  PIN Q[107]
    DIRECTION OUTPUT ;
    USE SIGNAL ;
    PORT
      LAYER M4 ;
        RECT 95.8500 279.4800 95.9500 280.0000 ;
    END
  END Q[107]
  PIN Q[106]
    DIRECTION OUTPUT ;
    USE SIGNAL ;
    PORT
      LAYER M4 ;
        RECT 97.4500 279.4800 97.5500 280.0000 ;
    END
  END Q[106]
  PIN Q[105]
    DIRECTION OUTPUT ;
    USE SIGNAL ;
    PORT
      LAYER M4 ;
        RECT 99.0500 279.4800 99.1500 280.0000 ;
    END
  END Q[105]
  PIN Q[104]
    DIRECTION OUTPUT ;
    USE SIGNAL ;
    PORT
      LAYER M4 ;
        RECT 100.6500 279.4800 100.7500 280.0000 ;
    END
  END Q[104]
  PIN Q[103]
    DIRECTION OUTPUT ;
    USE SIGNAL ;
    PORT
      LAYER M4 ;
        RECT 102.2500 279.4800 102.3500 280.0000 ;
    END
  END Q[103]
  PIN Q[102]
    DIRECTION OUTPUT ;
    USE SIGNAL ;
    PORT
      LAYER M4 ;
        RECT 103.8500 279.4800 103.9500 280.0000 ;
    END
  END Q[102]
  PIN Q[101]
    DIRECTION OUTPUT ;
    USE SIGNAL ;
    PORT
      LAYER M4 ;
        RECT 105.4500 279.4800 105.5500 280.0000 ;
    END
  END Q[101]
  PIN Q[100]
    DIRECTION OUTPUT ;
    USE SIGNAL ;
    PORT
      LAYER M4 ;
        RECT 107.0500 279.4800 107.1500 280.0000 ;
    END
  END Q[100]
  PIN Q[99]
    DIRECTION OUTPUT ;
    USE SIGNAL ;
    PORT
      LAYER M4 ;
        RECT 108.6500 279.4800 108.7500 280.0000 ;
    END
  END Q[99]
  PIN Q[98]
    DIRECTION OUTPUT ;
    USE SIGNAL ;
    PORT
      LAYER M4 ;
        RECT 110.2500 279.4800 110.3500 280.0000 ;
    END
  END Q[98]
  PIN Q[97]
    DIRECTION OUTPUT ;
    USE SIGNAL ;
    PORT
      LAYER M4 ;
        RECT 111.8500 279.4800 111.9500 280.0000 ;
    END
  END Q[97]
  PIN Q[96]
    DIRECTION OUTPUT ;
    USE SIGNAL ;
    PORT
      LAYER M4 ;
        RECT 113.4500 279.4800 113.5500 280.0000 ;
    END
  END Q[96]
  PIN Q[95]
    DIRECTION OUTPUT ;
    USE SIGNAL ;
    PORT
      LAYER M4 ;
        RECT 115.0500 279.4800 115.1500 280.0000 ;
    END
  END Q[95]
  PIN Q[94]
    DIRECTION OUTPUT ;
    USE SIGNAL ;
    PORT
      LAYER M4 ;
        RECT 116.6500 279.4800 116.7500 280.0000 ;
    END
  END Q[94]
  PIN Q[93]
    DIRECTION OUTPUT ;
    USE SIGNAL ;
    PORT
      LAYER M4 ;
        RECT 118.2500 279.4800 118.3500 280.0000 ;
    END
  END Q[93]
  PIN Q[92]
    DIRECTION OUTPUT ;
    USE SIGNAL ;
    PORT
      LAYER M4 ;
        RECT 119.8500 279.4800 119.9500 280.0000 ;
    END
  END Q[92]
  PIN Q[91]
    DIRECTION OUTPUT ;
    USE SIGNAL ;
    PORT
      LAYER M4 ;
        RECT 121.4500 279.4800 121.5500 280.0000 ;
    END
  END Q[91]
  PIN Q[90]
    DIRECTION OUTPUT ;
    USE SIGNAL ;
    PORT
      LAYER M4 ;
        RECT 123.0500 279.4800 123.1500 280.0000 ;
    END
  END Q[90]
  PIN Q[89]
    DIRECTION OUTPUT ;
    USE SIGNAL ;
    PORT
      LAYER M4 ;
        RECT 124.6500 279.4800 124.7500 280.0000 ;
    END
  END Q[89]
  PIN Q[88]
    DIRECTION OUTPUT ;
    USE SIGNAL ;
    PORT
      LAYER M4 ;
        RECT 126.2500 279.4800 126.3500 280.0000 ;
    END
  END Q[88]
  PIN Q[87]
    DIRECTION OUTPUT ;
    USE SIGNAL ;
    PORT
      LAYER M4 ;
        RECT 127.8500 279.4800 127.9500 280.0000 ;
    END
  END Q[87]
  PIN Q[86]
    DIRECTION OUTPUT ;
    USE SIGNAL ;
    PORT
      LAYER M4 ;
        RECT 129.4500 279.4800 129.5500 280.0000 ;
    END
  END Q[86]
  PIN Q[85]
    DIRECTION OUTPUT ;
    USE SIGNAL ;
    PORT
      LAYER M4 ;
        RECT 131.0500 279.4800 131.1500 280.0000 ;
    END
  END Q[85]
  PIN Q[84]
    DIRECTION OUTPUT ;
    USE SIGNAL ;
    PORT
      LAYER M4 ;
        RECT 132.6500 279.4800 132.7500 280.0000 ;
    END
  END Q[84]
  PIN Q[83]
    DIRECTION OUTPUT ;
    USE SIGNAL ;
    PORT
      LAYER M4 ;
        RECT 134.2500 279.4800 134.3500 280.0000 ;
    END
  END Q[83]
  PIN Q[82]
    DIRECTION OUTPUT ;
    USE SIGNAL ;
    PORT
      LAYER M4 ;
        RECT 135.8500 279.4800 135.9500 280.0000 ;
    END
  END Q[82]
  PIN Q[81]
    DIRECTION OUTPUT ;
    USE SIGNAL ;
    PORT
      LAYER M4 ;
        RECT 137.4500 279.4800 137.5500 280.0000 ;
    END
  END Q[81]
  PIN Q[80]
    DIRECTION OUTPUT ;
    USE SIGNAL ;
    PORT
      LAYER M4 ;
        RECT 139.0500 279.4800 139.1500 280.0000 ;
    END
  END Q[80]
  PIN Q[79]
    DIRECTION OUTPUT ;
    USE SIGNAL ;
    PORT
      LAYER M4 ;
        RECT 140.6500 279.4800 140.7500 280.0000 ;
    END
  END Q[79]
  PIN Q[78]
    DIRECTION OUTPUT ;
    USE SIGNAL ;
    PORT
      LAYER M4 ;
        RECT 142.2500 279.4800 142.3500 280.0000 ;
    END
  END Q[78]
  PIN Q[77]
    DIRECTION OUTPUT ;
    USE SIGNAL ;
    PORT
      LAYER M4 ;
        RECT 143.8500 279.4800 143.9500 280.0000 ;
    END
  END Q[77]
  PIN Q[76]
    DIRECTION OUTPUT ;
    USE SIGNAL ;
    PORT
      LAYER M4 ;
        RECT 145.4500 279.4800 145.5500 280.0000 ;
    END
  END Q[76]
  PIN Q[75]
    DIRECTION OUTPUT ;
    USE SIGNAL ;
    PORT
      LAYER M4 ;
        RECT 147.0500 279.4800 147.1500 280.0000 ;
    END
  END Q[75]
  PIN Q[74]
    DIRECTION OUTPUT ;
    USE SIGNAL ;
    PORT
      LAYER M4 ;
        RECT 148.6500 279.4800 148.7500 280.0000 ;
    END
  END Q[74]
  PIN Q[73]
    DIRECTION OUTPUT ;
    USE SIGNAL ;
    PORT
      LAYER M4 ;
        RECT 150.2500 279.4800 150.3500 280.0000 ;
    END
  END Q[73]
  PIN Q[72]
    DIRECTION OUTPUT ;
    USE SIGNAL ;
    PORT
      LAYER M4 ;
        RECT 151.8500 279.4800 151.9500 280.0000 ;
    END
  END Q[72]
  PIN Q[71]
    DIRECTION OUTPUT ;
    USE SIGNAL ;
    PORT
      LAYER M4 ;
        RECT 153.4500 279.4800 153.5500 280.0000 ;
    END
  END Q[71]
  PIN Q[70]
    DIRECTION OUTPUT ;
    USE SIGNAL ;
    PORT
      LAYER M4 ;
        RECT 155.0500 279.4800 155.1500 280.0000 ;
    END
  END Q[70]
  PIN Q[69]
    DIRECTION OUTPUT ;
    USE SIGNAL ;
    PORT
      LAYER M4 ;
        RECT 156.6500 279.4800 156.7500 280.0000 ;
    END
  END Q[69]
  PIN Q[68]
    DIRECTION OUTPUT ;
    USE SIGNAL ;
    PORT
      LAYER M4 ;
        RECT 158.2500 279.4800 158.3500 280.0000 ;
    END
  END Q[68]
  PIN Q[67]
    DIRECTION OUTPUT ;
    USE SIGNAL ;
    PORT
      LAYER M4 ;
        RECT 159.8500 279.4800 159.9500 280.0000 ;
    END
  END Q[67]
  PIN Q[66]
    DIRECTION OUTPUT ;
    USE SIGNAL ;
    PORT
      LAYER M4 ;
        RECT 161.4500 279.4800 161.5500 280.0000 ;
    END
  END Q[66]
  PIN Q[65]
    DIRECTION OUTPUT ;
    USE SIGNAL ;
    PORT
      LAYER M4 ;
        RECT 163.0500 279.4800 163.1500 280.0000 ;
    END
  END Q[65]
  PIN Q[64]
    DIRECTION OUTPUT ;
    USE SIGNAL ;
    PORT
      LAYER M4 ;
        RECT 164.6500 279.4800 164.7500 280.0000 ;
    END
  END Q[64]
  PIN Q[63]
    DIRECTION OUTPUT ;
    USE SIGNAL ;
    PORT
      LAYER M4 ;
        RECT 166.2500 279.4800 166.3500 280.0000 ;
    END
  END Q[63]
  PIN Q[62]
    DIRECTION OUTPUT ;
    USE SIGNAL ;
    PORT
      LAYER M4 ;
        RECT 167.8500 279.4800 167.9500 280.0000 ;
    END
  END Q[62]
  PIN Q[61]
    DIRECTION OUTPUT ;
    USE SIGNAL ;
    PORT
      LAYER M4 ;
        RECT 169.4500 279.4800 169.5500 280.0000 ;
    END
  END Q[61]
  PIN Q[60]
    DIRECTION OUTPUT ;
    USE SIGNAL ;
    PORT
      LAYER M4 ;
        RECT 171.0500 279.4800 171.1500 280.0000 ;
    END
  END Q[60]
  PIN Q[59]
    DIRECTION OUTPUT ;
    USE SIGNAL ;
    PORT
      LAYER M4 ;
        RECT 172.6500 279.4800 172.7500 280.0000 ;
    END
  END Q[59]
  PIN Q[58]
    DIRECTION OUTPUT ;
    USE SIGNAL ;
    PORT
      LAYER M4 ;
        RECT 174.2500 279.4800 174.3500 280.0000 ;
    END
  END Q[58]
  PIN Q[57]
    DIRECTION OUTPUT ;
    USE SIGNAL ;
    PORT
      LAYER M4 ;
        RECT 175.8500 279.4800 175.9500 280.0000 ;
    END
  END Q[57]
  PIN Q[56]
    DIRECTION OUTPUT ;
    USE SIGNAL ;
    PORT
      LAYER M4 ;
        RECT 177.4500 279.4800 177.5500 280.0000 ;
    END
  END Q[56]
  PIN Q[55]
    DIRECTION OUTPUT ;
    USE SIGNAL ;
    PORT
      LAYER M4 ;
        RECT 179.0500 279.4800 179.1500 280.0000 ;
    END
  END Q[55]
  PIN Q[54]
    DIRECTION OUTPUT ;
    USE SIGNAL ;
    PORT
      LAYER M4 ;
        RECT 180.6500 279.4800 180.7500 280.0000 ;
    END
  END Q[54]
  PIN Q[53]
    DIRECTION OUTPUT ;
    USE SIGNAL ;
    PORT
      LAYER M4 ;
        RECT 182.2500 279.4800 182.3500 280.0000 ;
    END
  END Q[53]
  PIN Q[52]
    DIRECTION OUTPUT ;
    USE SIGNAL ;
    PORT
      LAYER M4 ;
        RECT 183.8500 279.4800 183.9500 280.0000 ;
    END
  END Q[52]
  PIN Q[51]
    DIRECTION OUTPUT ;
    USE SIGNAL ;
    PORT
      LAYER M4 ;
        RECT 185.4500 279.4800 185.5500 280.0000 ;
    END
  END Q[51]
  PIN Q[50]
    DIRECTION OUTPUT ;
    USE SIGNAL ;
    PORT
      LAYER M4 ;
        RECT 187.0500 279.4800 187.1500 280.0000 ;
    END
  END Q[50]
  PIN Q[49]
    DIRECTION OUTPUT ;
    USE SIGNAL ;
    PORT
      LAYER M4 ;
        RECT 188.6500 279.4800 188.7500 280.0000 ;
    END
  END Q[49]
  PIN Q[48]
    DIRECTION OUTPUT ;
    USE SIGNAL ;
    PORT
      LAYER M4 ;
        RECT 190.2500 279.4800 190.3500 280.0000 ;
    END
  END Q[48]
  PIN Q[47]
    DIRECTION OUTPUT ;
    USE SIGNAL ;
    PORT
      LAYER M4 ;
        RECT 191.8500 279.4800 191.9500 280.0000 ;
    END
  END Q[47]
  PIN Q[46]
    DIRECTION OUTPUT ;
    USE SIGNAL ;
    PORT
      LAYER M4 ;
        RECT 193.4500 279.4800 193.5500 280.0000 ;
    END
  END Q[46]
  PIN Q[45]
    DIRECTION OUTPUT ;
    USE SIGNAL ;
    PORT
      LAYER M4 ;
        RECT 195.0500 279.4800 195.1500 280.0000 ;
    END
  END Q[45]
  PIN Q[44]
    DIRECTION OUTPUT ;
    USE SIGNAL ;
    PORT
      LAYER M4 ;
        RECT 196.6500 279.4800 196.7500 280.0000 ;
    END
  END Q[44]
  PIN Q[43]
    DIRECTION OUTPUT ;
    USE SIGNAL ;
    PORT
      LAYER M4 ;
        RECT 198.2500 279.4800 198.3500 280.0000 ;
    END
  END Q[43]
  PIN Q[42]
    DIRECTION OUTPUT ;
    USE SIGNAL ;
    PORT
      LAYER M4 ;
        RECT 199.8500 279.4800 199.9500 280.0000 ;
    END
  END Q[42]
  PIN Q[41]
    DIRECTION OUTPUT ;
    USE SIGNAL ;
    PORT
      LAYER M4 ;
        RECT 201.4500 279.4800 201.5500 280.0000 ;
    END
  END Q[41]
  PIN Q[40]
    DIRECTION OUTPUT ;
    USE SIGNAL ;
    PORT
      LAYER M4 ;
        RECT 203.0500 279.4800 203.1500 280.0000 ;
    END
  END Q[40]
  PIN Q[39]
    DIRECTION OUTPUT ;
    USE SIGNAL ;
    PORT
      LAYER M4 ;
        RECT 204.6500 279.4800 204.7500 280.0000 ;
    END
  END Q[39]
  PIN Q[38]
    DIRECTION OUTPUT ;
    USE SIGNAL ;
    PORT
      LAYER M4 ;
        RECT 206.2500 279.4800 206.3500 280.0000 ;
    END
  END Q[38]
  PIN Q[37]
    DIRECTION OUTPUT ;
    USE SIGNAL ;
    PORT
      LAYER M4 ;
        RECT 207.8500 279.4800 207.9500 280.0000 ;
    END
  END Q[37]
  PIN Q[36]
    DIRECTION OUTPUT ;
    USE SIGNAL ;
    PORT
      LAYER M4 ;
        RECT 209.4500 279.4800 209.5500 280.0000 ;
    END
  END Q[36]
  PIN Q[35]
    DIRECTION OUTPUT ;
    USE SIGNAL ;
    PORT
      LAYER M4 ;
        RECT 211.0500 279.4800 211.1500 280.0000 ;
    END
  END Q[35]
  PIN Q[34]
    DIRECTION OUTPUT ;
    USE SIGNAL ;
    PORT
      LAYER M4 ;
        RECT 212.6500 279.4800 212.7500 280.0000 ;
    END
  END Q[34]
  PIN Q[33]
    DIRECTION OUTPUT ;
    USE SIGNAL ;
    PORT
      LAYER M4 ;
        RECT 214.2500 279.4800 214.3500 280.0000 ;
    END
  END Q[33]
  PIN Q[32]
    DIRECTION OUTPUT ;
    USE SIGNAL ;
    PORT
      LAYER M4 ;
        RECT 215.8500 279.4800 215.9500 280.0000 ;
    END
  END Q[32]
  PIN Q[31]
    DIRECTION OUTPUT ;
    USE SIGNAL ;
    PORT
      LAYER M4 ;
        RECT 217.4500 279.4800 217.5500 280.0000 ;
    END
  END Q[31]
  PIN Q[30]
    DIRECTION OUTPUT ;
    USE SIGNAL ;
    PORT
      LAYER M4 ;
        RECT 219.0500 279.4800 219.1500 280.0000 ;
    END
  END Q[30]
  PIN Q[29]
    DIRECTION OUTPUT ;
    USE SIGNAL ;
    PORT
      LAYER M4 ;
        RECT 220.6500 279.4800 220.7500 280.0000 ;
    END
  END Q[29]
  PIN Q[28]
    DIRECTION OUTPUT ;
    USE SIGNAL ;
    PORT
      LAYER M4 ;
        RECT 222.2500 279.4800 222.3500 280.0000 ;
    END
  END Q[28]
  PIN Q[27]
    DIRECTION OUTPUT ;
    USE SIGNAL ;
    PORT
      LAYER M4 ;
        RECT 223.8500 279.4800 223.9500 280.0000 ;
    END
  END Q[27]
  PIN Q[26]
    DIRECTION OUTPUT ;
    USE SIGNAL ;
    PORT
      LAYER M4 ;
        RECT 225.4500 279.4800 225.5500 280.0000 ;
    END
  END Q[26]
  PIN Q[25]
    DIRECTION OUTPUT ;
    USE SIGNAL ;
    PORT
      LAYER M4 ;
        RECT 227.0500 279.4800 227.1500 280.0000 ;
    END
  END Q[25]
  PIN Q[24]
    DIRECTION OUTPUT ;
    USE SIGNAL ;
    PORT
      LAYER M4 ;
        RECT 228.6500 279.4800 228.7500 280.0000 ;
    END
  END Q[24]
  PIN Q[23]
    DIRECTION OUTPUT ;
    USE SIGNAL ;
    PORT
      LAYER M4 ;
        RECT 230.2500 279.4800 230.3500 280.0000 ;
    END
  END Q[23]
  PIN Q[22]
    DIRECTION OUTPUT ;
    USE SIGNAL ;
    PORT
      LAYER M4 ;
        RECT 231.8500 279.4800 231.9500 280.0000 ;
    END
  END Q[22]
  PIN Q[21]
    DIRECTION OUTPUT ;
    USE SIGNAL ;
    PORT
      LAYER M4 ;
        RECT 233.4500 279.4800 233.5500 280.0000 ;
    END
  END Q[21]
  PIN Q[20]
    DIRECTION OUTPUT ;
    USE SIGNAL ;
    PORT
      LAYER M4 ;
        RECT 235.0500 279.4800 235.1500 280.0000 ;
    END
  END Q[20]
  PIN Q[19]
    DIRECTION OUTPUT ;
    USE SIGNAL ;
    PORT
      LAYER M4 ;
        RECT 236.6500 279.4800 236.7500 280.0000 ;
    END
  END Q[19]
  PIN Q[18]
    DIRECTION OUTPUT ;
    USE SIGNAL ;
    PORT
      LAYER M4 ;
        RECT 238.2500 279.4800 238.3500 280.0000 ;
    END
  END Q[18]
  PIN Q[17]
    DIRECTION OUTPUT ;
    USE SIGNAL ;
    PORT
      LAYER M4 ;
        RECT 239.8500 279.4800 239.9500 280.0000 ;
    END
  END Q[17]
  PIN Q[16]
    DIRECTION OUTPUT ;
    USE SIGNAL ;
    PORT
      LAYER M4 ;
        RECT 241.4500 279.4800 241.5500 280.0000 ;
    END
  END Q[16]
  PIN Q[15]
    DIRECTION OUTPUT ;
    USE SIGNAL ;
    PORT
      LAYER M4 ;
        RECT 243.0500 279.4800 243.1500 280.0000 ;
    END
  END Q[15]
  PIN Q[14]
    DIRECTION OUTPUT ;
    USE SIGNAL ;
    PORT
      LAYER M4 ;
        RECT 244.6500 279.4800 244.7500 280.0000 ;
    END
  END Q[14]
  PIN Q[13]
    DIRECTION OUTPUT ;
    USE SIGNAL ;
    PORT
      LAYER M4 ;
        RECT 246.2500 279.4800 246.3500 280.0000 ;
    END
  END Q[13]
  PIN Q[12]
    DIRECTION OUTPUT ;
    USE SIGNAL ;
    PORT
      LAYER M4 ;
        RECT 247.8500 279.4800 247.9500 280.0000 ;
    END
  END Q[12]
  PIN Q[11]
    DIRECTION OUTPUT ;
    USE SIGNAL ;
    PORT
      LAYER M4 ;
        RECT 249.4500 279.4800 249.5500 280.0000 ;
    END
  END Q[11]
  PIN Q[10]
    DIRECTION OUTPUT ;
    USE SIGNAL ;
    PORT
      LAYER M4 ;
        RECT 251.0500 279.4800 251.1500 280.0000 ;
    END
  END Q[10]
  PIN Q[9]
    DIRECTION OUTPUT ;
    USE SIGNAL ;
    PORT
      LAYER M4 ;
        RECT 252.6500 279.4800 252.7500 280.0000 ;
    END
  END Q[9]
  PIN Q[8]
    DIRECTION OUTPUT ;
    USE SIGNAL ;
    PORT
      LAYER M4 ;
        RECT 254.2500 279.4800 254.3500 280.0000 ;
    END
  END Q[8]
  PIN Q[7]
    DIRECTION OUTPUT ;
    USE SIGNAL ;
    PORT
      LAYER M4 ;
        RECT 255.8500 279.4800 255.9500 280.0000 ;
    END
  END Q[7]
  PIN Q[6]
    DIRECTION OUTPUT ;
    USE SIGNAL ;
    PORT
      LAYER M4 ;
        RECT 257.4500 279.4800 257.5500 280.0000 ;
    END
  END Q[6]
  PIN Q[5]
    DIRECTION OUTPUT ;
    USE SIGNAL ;
    PORT
      LAYER M4 ;
        RECT 259.0500 279.4800 259.1500 280.0000 ;
    END
  END Q[5]
  PIN Q[4]
    DIRECTION OUTPUT ;
    USE SIGNAL ;
    PORT
      LAYER M4 ;
        RECT 260.6500 279.4800 260.7500 280.0000 ;
    END
  END Q[4]
  PIN Q[3]
    DIRECTION OUTPUT ;
    USE SIGNAL ;
    PORT
      LAYER M4 ;
        RECT 262.2500 279.4800 262.3500 280.0000 ;
    END
  END Q[3]
  PIN Q[2]
    DIRECTION OUTPUT ;
    USE SIGNAL ;
    PORT
      LAYER M4 ;
        RECT 263.8500 279.4800 263.9500 280.0000 ;
    END
  END Q[2]
  PIN Q[1]
    DIRECTION OUTPUT ;
    USE SIGNAL ;
    PORT
      LAYER M4 ;
        RECT 265.4500 279.4800 265.5500 280.0000 ;
    END
  END Q[1]
  PIN Q[0]
    DIRECTION OUTPUT ;
    USE SIGNAL ;
    PORT
      LAYER M4 ;
        RECT 267.0500 279.4800 267.1500 280.0000 ;
    END
  END Q[0]
  PIN CEN
    DIRECTION INPUT ;
    USE SIGNAL ;
    PORT
      LAYER M3 ;
        RECT 0.0000 136.1500 0.5200 136.2500 ;
    END
  END CEN
  PIN WEN
    DIRECTION INPUT ;
    USE SIGNAL ;
    PORT
      LAYER M3 ;
        RECT 0.0000 128.1500 0.5200 128.2500 ;
    END
  END WEN
  PIN A[3]
    DIRECTION INPUT ;
    USE SIGNAL ;
    PORT
      LAYER M3 ;
        RECT 0.0000 152.1500 0.5200 152.2500 ;
    END
  END A[3]
  PIN A[2]
    DIRECTION INPUT ;
    USE SIGNAL ;
    PORT
      LAYER M3 ;
        RECT 0.0000 148.1500 0.5200 148.2500 ;
    END
  END A[2]
  PIN A[1]
    DIRECTION INPUT ;
    USE SIGNAL ;
    PORT
      LAYER M3 ;
        RECT 0.0000 144.1500 0.5200 144.2500 ;
    END
  END A[1]
  PIN A[0]
    DIRECTION INPUT ;
    USE SIGNAL ;
    PORT
      LAYER M3 ;
        RECT 0.0000 140.1500 0.5200 140.2500 ;
    END
  END A[0]
  PIN VSS
    DIRECTION INOUT ;
    USE GROUND ;

# P/G power stripe data as pin
    PORT
      LAYER M4 ;
        RECT 20.0000 15.0000 21.0000 265.0000 ;
        RECT 26.9700 15.0000 27.9700 265.0000 ;
        RECT 33.9400 15.0000 34.9400 265.0000 ;
        RECT 40.9100 15.0000 41.9100 265.0000 ;
        RECT 47.8800 15.0000 48.8800 265.0000 ;
        RECT 54.8500 15.0000 55.8500 265.0000 ;
        RECT 61.8200 15.0000 62.8200 265.0000 ;
        RECT 68.7900 15.0000 69.7900 265.0000 ;
        RECT 75.7600 15.0000 76.7600 265.0000 ;
        RECT 82.7300 15.0000 83.7300 265.0000 ;
        RECT 89.7000 15.0000 90.7000 265.0000 ;
        RECT 96.6700 15.0000 97.6700 265.0000 ;
        RECT 103.6400 15.0000 104.6400 265.0000 ;
        RECT 110.6100 15.0000 111.6100 265.0000 ;
        RECT 117.5800 15.0000 118.5800 265.0000 ;
        RECT 124.5500 15.0000 125.5500 265.0000 ;
        RECT 131.5200 15.0000 132.5200 265.0000 ;
        RECT 138.4900 15.0000 139.4900 265.0000 ;
        RECT 145.4600 15.0000 146.4600 265.0000 ;
        RECT 152.4300 15.0000 153.4300 265.0000 ;
        RECT 159.4000 15.0000 160.4000 265.0000 ;
        RECT 166.3700 15.0000 167.3700 265.0000 ;
        RECT 173.3400 15.0000 174.3400 265.0000 ;
        RECT 180.3100 15.0000 181.3100 265.0000 ;
        RECT 187.2800 15.0000 188.2800 265.0000 ;
        RECT 194.2500 15.0000 195.2500 265.0000 ;
        RECT 201.2200 15.0000 202.2200 265.0000 ;
        RECT 208.1900 15.0000 209.1900 265.0000 ;
        RECT 256.9800 15.0000 257.9800 265.0000 ;
        RECT 250.0100 15.0000 251.0100 265.0000 ;
        RECT 243.0400 15.0000 244.0400 265.0000 ;
        RECT 236.0700 15.0000 237.0700 265.0000 ;
        RECT 215.1600 15.0000 216.1600 265.0000 ;
        RECT 222.1300 15.0000 223.1300 265.0000 ;
        RECT 229.1000 15.0000 230.1000 265.0000 ;
    END
# end of P/G power stripe data as pin

  END VSS
  PIN VDD
    DIRECTION INOUT ;
    USE POWER ;

# P/G power stripe data as pin
    PORT
      LAYER M4 ;
        RECT 63.8200 15.0000 64.8200 265.0000 ;
        RECT 56.8500 15.0000 57.8500 265.0000 ;
        RECT 49.8800 15.0000 50.8800 265.0000 ;
        RECT 42.9100 15.0000 43.9100 265.0000 ;
        RECT 35.9400 15.0000 36.9400 265.0000 ;
        RECT 28.9700 15.0000 29.9700 265.0000 ;
        RECT 22.0000 15.0000 23.0000 265.0000 ;
        RECT 98.6700 15.0000 99.6700 265.0000 ;
        RECT 91.7000 15.0000 92.7000 265.0000 ;
        RECT 84.7300 15.0000 85.7300 265.0000 ;
        RECT 77.7600 15.0000 78.7600 265.0000 ;
        RECT 70.7900 15.0000 71.7900 265.0000 ;
        RECT 105.6400 15.0000 106.6400 265.0000 ;
        RECT 112.6100 15.0000 113.6100 265.0000 ;
        RECT 119.5800 15.0000 120.5800 265.0000 ;
        RECT 126.5500 15.0000 127.5500 265.0000 ;
        RECT 133.5200 15.0000 134.5200 265.0000 ;
        RECT 203.2200 15.0000 204.2200 265.0000 ;
        RECT 196.2500 15.0000 197.2500 265.0000 ;
        RECT 189.2800 15.0000 190.2800 265.0000 ;
        RECT 182.3100 15.0000 183.3100 265.0000 ;
        RECT 175.3400 15.0000 176.3400 265.0000 ;
        RECT 168.3700 15.0000 169.3700 265.0000 ;
        RECT 161.4000 15.0000 162.4000 265.0000 ;
        RECT 154.4300 15.0000 155.4300 265.0000 ;
        RECT 147.4600 15.0000 148.4600 265.0000 ;
        RECT 140.4900 15.0000 141.4900 265.0000 ;
        RECT 224.1300 15.0000 225.1300 265.0000 ;
        RECT 217.1600 15.0000 218.1600 265.0000 ;
        RECT 210.1900 15.0000 211.1900 265.0000 ;
        RECT 231.1000 15.0000 232.1000 265.0000 ;
        RECT 238.0700 15.0000 239.0700 265.0000 ;
        RECT 245.0400 15.0000 246.0400 265.0000 ;
        RECT 252.0100 15.0000 253.0100 265.0000 ;
        RECT 258.9800 15.0000 259.9800 265.0000 ;
        RECT 28.9700 14.8350 29.9700 15.1650 ;
        RECT 22.0000 14.8350 23.0000 15.1650 ;
        RECT 49.8800 14.8350 50.8800 15.1650 ;
        RECT 42.9100 14.8350 43.9100 15.1650 ;
        RECT 35.9400 14.8350 36.9400 15.1650 ;
        RECT 63.8200 14.8350 64.8200 15.1650 ;
        RECT 56.8500 14.8350 57.8500 15.1650 ;
        RECT 84.7300 14.8350 85.7300 15.1650 ;
        RECT 77.7600 14.8350 78.7600 15.1650 ;
        RECT 70.7900 14.8350 71.7900 15.1650 ;
        RECT 98.6700 14.8350 99.6700 15.1650 ;
        RECT 91.7000 14.8350 92.7000 15.1650 ;
        RECT 119.5800 14.8350 120.5800 15.1650 ;
        RECT 112.6100 14.8350 113.6100 15.1650 ;
        RECT 105.6400 14.8350 106.6400 15.1650 ;
        RECT 133.5200 14.8350 134.5200 15.1650 ;
        RECT 126.5500 14.8350 127.5500 15.1650 ;
        RECT 154.4300 14.8350 155.4300 15.1650 ;
        RECT 147.4600 14.8350 148.4600 15.1650 ;
        RECT 140.4900 14.8350 141.4900 15.1650 ;
        RECT 168.3700 14.8350 169.3700 15.1650 ;
        RECT 161.4000 14.8350 162.4000 15.1650 ;
        RECT 189.2800 14.8350 190.2800 15.1650 ;
        RECT 182.3100 14.8350 183.3100 15.1650 ;
        RECT 175.3400 14.8350 176.3400 15.1650 ;
        RECT 203.2200 14.8350 204.2200 15.1650 ;
        RECT 196.2500 14.8350 197.2500 15.1650 ;
        RECT 224.1300 14.8350 225.1300 15.1650 ;
        RECT 217.1600 14.8350 218.1600 15.1650 ;
        RECT 210.1900 14.8350 211.1900 15.1650 ;
        RECT 238.0700 14.8350 239.0700 15.1650 ;
        RECT 231.1000 14.8350 232.1000 15.1650 ;
        RECT 258.9800 14.8350 259.9800 15.1650 ;
        RECT 252.0100 14.8350 253.0100 15.1650 ;
        RECT 245.0400 14.8350 246.0400 15.1650 ;
    END
# end of P/G power stripe data as pin

  END VDD
  OBS
    LAYER M1 ;
      RECT 0.0000 0.0000 280.0000 280.0000 ;
    LAYER M2 ;
      RECT 0.0000 0.0000 280.0000 280.0000 ;
    LAYER M3 ;
      RECT 0.0000 152.3500 280.0000 280.0000 ;
      RECT 0.6200 152.0500 280.0000 152.3500 ;
      RECT 0.0000 148.3500 280.0000 152.0500 ;
      RECT 0.6200 148.0500 280.0000 148.3500 ;
      RECT 0.0000 144.3500 280.0000 148.0500 ;
      RECT 0.6200 144.0500 280.0000 144.3500 ;
      RECT 0.0000 140.3500 280.0000 144.0500 ;
      RECT 0.6200 140.0500 280.0000 140.3500 ;
      RECT 0.0000 136.3500 280.0000 140.0500 ;
      RECT 0.6200 136.0500 280.0000 136.3500 ;
      RECT 0.0000 132.3500 280.0000 136.0500 ;
      RECT 0.6200 132.0500 280.0000 132.3500 ;
      RECT 0.0000 128.3500 280.0000 132.0500 ;
      RECT 0.6200 128.0500 280.0000 128.3500 ;
      RECT 0.0000 0.0000 280.0000 128.0500 ;
    LAYER M4 ;
      RECT 267.2500 279.3800 280.0000 280.0000 ;
      RECT 265.6500 279.3800 266.9500 280.0000 ;
      RECT 264.0500 279.3800 265.3500 280.0000 ;
      RECT 262.4500 279.3800 263.7500 280.0000 ;
      RECT 260.8500 279.3800 262.1500 280.0000 ;
      RECT 259.2500 279.3800 260.5500 280.0000 ;
      RECT 257.6500 279.3800 258.9500 280.0000 ;
      RECT 256.0500 279.3800 257.3500 280.0000 ;
      RECT 254.4500 279.3800 255.7500 280.0000 ;
      RECT 252.8500 279.3800 254.1500 280.0000 ;
      RECT 251.2500 279.3800 252.5500 280.0000 ;
      RECT 249.6500 279.3800 250.9500 280.0000 ;
      RECT 248.0500 279.3800 249.3500 280.0000 ;
      RECT 246.4500 279.3800 247.7500 280.0000 ;
      RECT 244.8500 279.3800 246.1500 280.0000 ;
      RECT 243.2500 279.3800 244.5500 280.0000 ;
      RECT 241.6500 279.3800 242.9500 280.0000 ;
      RECT 240.0500 279.3800 241.3500 280.0000 ;
      RECT 238.4500 279.3800 239.7500 280.0000 ;
      RECT 236.8500 279.3800 238.1500 280.0000 ;
      RECT 235.2500 279.3800 236.5500 280.0000 ;
      RECT 233.6500 279.3800 234.9500 280.0000 ;
      RECT 232.0500 279.3800 233.3500 280.0000 ;
      RECT 230.4500 279.3800 231.7500 280.0000 ;
      RECT 228.8500 279.3800 230.1500 280.0000 ;
      RECT 227.2500 279.3800 228.5500 280.0000 ;
      RECT 225.6500 279.3800 226.9500 280.0000 ;
      RECT 224.0500 279.3800 225.3500 280.0000 ;
      RECT 222.4500 279.3800 223.7500 280.0000 ;
      RECT 220.8500 279.3800 222.1500 280.0000 ;
      RECT 219.2500 279.3800 220.5500 280.0000 ;
      RECT 217.6500 279.3800 218.9500 280.0000 ;
      RECT 216.0500 279.3800 217.3500 280.0000 ;
      RECT 214.4500 279.3800 215.7500 280.0000 ;
      RECT 212.8500 279.3800 214.1500 280.0000 ;
      RECT 211.2500 279.3800 212.5500 280.0000 ;
      RECT 209.6500 279.3800 210.9500 280.0000 ;
      RECT 208.0500 279.3800 209.3500 280.0000 ;
      RECT 206.4500 279.3800 207.7500 280.0000 ;
      RECT 204.8500 279.3800 206.1500 280.0000 ;
      RECT 203.2500 279.3800 204.5500 280.0000 ;
      RECT 201.6500 279.3800 202.9500 280.0000 ;
      RECT 200.0500 279.3800 201.3500 280.0000 ;
      RECT 198.4500 279.3800 199.7500 280.0000 ;
      RECT 196.8500 279.3800 198.1500 280.0000 ;
      RECT 195.2500 279.3800 196.5500 280.0000 ;
      RECT 193.6500 279.3800 194.9500 280.0000 ;
      RECT 192.0500 279.3800 193.3500 280.0000 ;
      RECT 190.4500 279.3800 191.7500 280.0000 ;
      RECT 188.8500 279.3800 190.1500 280.0000 ;
      RECT 187.2500 279.3800 188.5500 280.0000 ;
      RECT 185.6500 279.3800 186.9500 280.0000 ;
      RECT 184.0500 279.3800 185.3500 280.0000 ;
      RECT 182.4500 279.3800 183.7500 280.0000 ;
      RECT 180.8500 279.3800 182.1500 280.0000 ;
      RECT 179.2500 279.3800 180.5500 280.0000 ;
      RECT 177.6500 279.3800 178.9500 280.0000 ;
      RECT 176.0500 279.3800 177.3500 280.0000 ;
      RECT 174.4500 279.3800 175.7500 280.0000 ;
      RECT 172.8500 279.3800 174.1500 280.0000 ;
      RECT 171.2500 279.3800 172.5500 280.0000 ;
      RECT 169.6500 279.3800 170.9500 280.0000 ;
      RECT 168.0500 279.3800 169.3500 280.0000 ;
      RECT 166.4500 279.3800 167.7500 280.0000 ;
      RECT 164.8500 279.3800 166.1500 280.0000 ;
      RECT 163.2500 279.3800 164.5500 280.0000 ;
      RECT 161.6500 279.3800 162.9500 280.0000 ;
      RECT 160.0500 279.3800 161.3500 280.0000 ;
      RECT 158.4500 279.3800 159.7500 280.0000 ;
      RECT 156.8500 279.3800 158.1500 280.0000 ;
      RECT 155.2500 279.3800 156.5500 280.0000 ;
      RECT 153.6500 279.3800 154.9500 280.0000 ;
      RECT 152.0500 279.3800 153.3500 280.0000 ;
      RECT 150.4500 279.3800 151.7500 280.0000 ;
      RECT 148.8500 279.3800 150.1500 280.0000 ;
      RECT 147.2500 279.3800 148.5500 280.0000 ;
      RECT 145.6500 279.3800 146.9500 280.0000 ;
      RECT 144.0500 279.3800 145.3500 280.0000 ;
      RECT 142.4500 279.3800 143.7500 280.0000 ;
      RECT 140.8500 279.3800 142.1500 280.0000 ;
      RECT 139.2500 279.3800 140.5500 280.0000 ;
      RECT 137.6500 279.3800 138.9500 280.0000 ;
      RECT 136.0500 279.3800 137.3500 280.0000 ;
      RECT 134.4500 279.3800 135.7500 280.0000 ;
      RECT 132.8500 279.3800 134.1500 280.0000 ;
      RECT 131.2500 279.3800 132.5500 280.0000 ;
      RECT 129.6500 279.3800 130.9500 280.0000 ;
      RECT 128.0500 279.3800 129.3500 280.0000 ;
      RECT 126.4500 279.3800 127.7500 280.0000 ;
      RECT 124.8500 279.3800 126.1500 280.0000 ;
      RECT 123.2500 279.3800 124.5500 280.0000 ;
      RECT 121.6500 279.3800 122.9500 280.0000 ;
      RECT 120.0500 279.3800 121.3500 280.0000 ;
      RECT 118.4500 279.3800 119.7500 280.0000 ;
      RECT 116.8500 279.3800 118.1500 280.0000 ;
      RECT 115.2500 279.3800 116.5500 280.0000 ;
      RECT 113.6500 279.3800 114.9500 280.0000 ;
      RECT 112.0500 279.3800 113.3500 280.0000 ;
      RECT 110.4500 279.3800 111.7500 280.0000 ;
      RECT 108.8500 279.3800 110.1500 280.0000 ;
      RECT 107.2500 279.3800 108.5500 280.0000 ;
      RECT 105.6500 279.3800 106.9500 280.0000 ;
      RECT 104.0500 279.3800 105.3500 280.0000 ;
      RECT 102.4500 279.3800 103.7500 280.0000 ;
      RECT 100.8500 279.3800 102.1500 280.0000 ;
      RECT 99.2500 279.3800 100.5500 280.0000 ;
      RECT 97.6500 279.3800 98.9500 280.0000 ;
      RECT 96.0500 279.3800 97.3500 280.0000 ;
      RECT 94.4500 279.3800 95.7500 280.0000 ;
      RECT 92.8500 279.3800 94.1500 280.0000 ;
      RECT 91.2500 279.3800 92.5500 280.0000 ;
      RECT 89.6500 279.3800 90.9500 280.0000 ;
      RECT 88.0500 279.3800 89.3500 280.0000 ;
      RECT 86.4500 279.3800 87.7500 280.0000 ;
      RECT 84.8500 279.3800 86.1500 280.0000 ;
      RECT 83.2500 279.3800 84.5500 280.0000 ;
      RECT 81.6500 279.3800 82.9500 280.0000 ;
      RECT 80.0500 279.3800 81.3500 280.0000 ;
      RECT 78.4500 279.3800 79.7500 280.0000 ;
      RECT 76.8500 279.3800 78.1500 280.0000 ;
      RECT 75.2500 279.3800 76.5500 280.0000 ;
      RECT 73.6500 279.3800 74.9500 280.0000 ;
      RECT 72.0500 279.3800 73.3500 280.0000 ;
      RECT 70.4500 279.3800 71.7500 280.0000 ;
      RECT 68.8500 279.3800 70.1500 280.0000 ;
      RECT 67.2500 279.3800 68.5500 280.0000 ;
      RECT 65.6500 279.3800 66.9500 280.0000 ;
      RECT 64.0500 279.3800 65.3500 280.0000 ;
      RECT 62.4500 279.3800 63.7500 280.0000 ;
      RECT 60.8500 279.3800 62.1500 280.0000 ;
      RECT 59.2500 279.3800 60.5500 280.0000 ;
      RECT 57.6500 279.3800 58.9500 280.0000 ;
      RECT 56.0500 279.3800 57.3500 280.0000 ;
      RECT 54.4500 279.3800 55.7500 280.0000 ;
      RECT 52.8500 279.3800 54.1500 280.0000 ;
      RECT 51.2500 279.3800 52.5500 280.0000 ;
      RECT 49.6500 279.3800 50.9500 280.0000 ;
      RECT 48.0500 279.3800 49.3500 280.0000 ;
      RECT 46.4500 279.3800 47.7500 280.0000 ;
      RECT 44.8500 279.3800 46.1500 280.0000 ;
      RECT 43.2500 279.3800 44.5500 280.0000 ;
      RECT 41.6500 279.3800 42.9500 280.0000 ;
      RECT 40.0500 279.3800 41.3500 280.0000 ;
      RECT 38.4500 279.3800 39.7500 280.0000 ;
      RECT 36.8500 279.3800 38.1500 280.0000 ;
      RECT 35.2500 279.3800 36.5500 280.0000 ;
      RECT 33.6500 279.3800 34.9500 280.0000 ;
      RECT 32.0500 279.3800 33.3500 280.0000 ;
      RECT 30.4500 279.3800 31.7500 280.0000 ;
      RECT 28.8500 279.3800 30.1500 280.0000 ;
      RECT 27.2500 279.3800 28.5500 280.0000 ;
      RECT 25.6500 279.3800 26.9500 280.0000 ;
      RECT 24.0500 279.3800 25.3500 280.0000 ;
      RECT 22.4500 279.3800 23.7500 280.0000 ;
      RECT 20.8500 279.3800 22.1500 280.0000 ;
      RECT 19.2500 279.3800 20.5500 280.0000 ;
      RECT 17.6500 279.3800 18.9500 280.0000 ;
      RECT 16.0500 279.3800 17.3500 280.0000 ;
      RECT 14.4500 279.3800 15.7500 280.0000 ;
      RECT 12.8500 279.3800 14.1500 280.0000 ;
      RECT 0.0000 279.3800 12.5500 280.0000 ;
      RECT 0.0000 265.1600 280.0000 279.3800 ;
      RECT 258.1400 14.8400 258.8200 265.1600 ;
      RECT 253.1700 14.8400 256.8200 265.1600 ;
      RECT 251.1700 14.8400 251.8500 265.1600 ;
      RECT 246.2000 14.8400 249.8500 265.1600 ;
      RECT 244.2000 14.8400 244.8800 265.1600 ;
      RECT 239.2300 14.8400 242.8800 265.1600 ;
      RECT 237.2300 14.8400 237.9100 265.1600 ;
      RECT 232.2600 14.8400 235.9100 265.1600 ;
      RECT 230.2600 14.8400 230.9400 265.1600 ;
      RECT 225.2900 14.8400 228.9400 265.1600 ;
      RECT 223.2900 14.8400 223.9700 265.1600 ;
      RECT 218.3200 14.8400 221.9700 265.1600 ;
      RECT 216.3200 14.8400 217.0000 265.1600 ;
      RECT 211.3500 14.8400 215.0000 265.1600 ;
      RECT 209.3500 14.8400 210.0300 265.1600 ;
      RECT 204.3800 14.8400 208.0300 265.1600 ;
      RECT 202.3800 14.8400 203.0600 265.1600 ;
      RECT 197.4100 14.8400 201.0600 265.1600 ;
      RECT 195.4100 14.8400 196.0900 265.1600 ;
      RECT 190.4400 14.8400 194.0900 265.1600 ;
      RECT 188.4400 14.8400 189.1200 265.1600 ;
      RECT 183.4700 14.8400 187.1200 265.1600 ;
      RECT 181.4700 14.8400 182.1500 265.1600 ;
      RECT 176.5000 14.8400 180.1500 265.1600 ;
      RECT 174.5000 14.8400 175.1800 265.1600 ;
      RECT 169.5300 14.8400 173.1800 265.1600 ;
      RECT 167.5300 14.8400 168.2100 265.1600 ;
      RECT 162.5600 14.8400 166.2100 265.1600 ;
      RECT 160.5600 14.8400 161.2400 265.1600 ;
      RECT 155.5900 14.8400 159.2400 265.1600 ;
      RECT 153.5900 14.8400 154.2700 265.1600 ;
      RECT 148.6200 14.8400 152.2700 265.1600 ;
      RECT 146.6200 14.8400 147.3000 265.1600 ;
      RECT 141.6500 14.8400 145.3000 265.1600 ;
      RECT 139.6500 14.8400 140.3300 265.1600 ;
      RECT 134.6800 14.8400 138.3300 265.1600 ;
      RECT 132.6800 14.8400 133.3600 265.1600 ;
      RECT 127.7100 14.8400 131.3600 265.1600 ;
      RECT 125.7100 14.8400 126.3900 265.1600 ;
      RECT 120.7400 14.8400 124.3900 265.1600 ;
      RECT 118.7400 14.8400 119.4200 265.1600 ;
      RECT 113.7700 14.8400 117.4200 265.1600 ;
      RECT 111.7700 14.8400 112.4500 265.1600 ;
      RECT 106.8000 14.8400 110.4500 265.1600 ;
      RECT 104.8000 14.8400 105.4800 265.1600 ;
      RECT 99.8300 14.8400 103.4800 265.1600 ;
      RECT 97.8300 14.8400 98.5100 265.1600 ;
      RECT 92.8600 14.8400 96.5100 265.1600 ;
      RECT 90.8600 14.8400 91.5400 265.1600 ;
      RECT 85.8900 14.8400 89.5400 265.1600 ;
      RECT 83.8900 14.8400 84.5700 265.1600 ;
      RECT 78.9200 14.8400 82.5700 265.1600 ;
      RECT 76.9200 14.8400 77.6000 265.1600 ;
      RECT 71.9500 14.8400 75.6000 265.1600 ;
      RECT 69.9500 14.8400 70.6300 265.1600 ;
      RECT 64.9800 14.8400 68.6300 265.1600 ;
      RECT 62.9800 14.8400 63.6600 265.1600 ;
      RECT 58.0100 14.8400 61.6600 265.1600 ;
      RECT 56.0100 14.8400 56.6900 265.1600 ;
      RECT 51.0400 14.8400 54.6900 265.1600 ;
      RECT 49.0400 14.8400 49.7200 265.1600 ;
      RECT 44.0700 14.8400 47.7200 265.1600 ;
      RECT 42.0700 14.8400 42.7500 265.1600 ;
      RECT 37.1000 14.8400 40.7500 265.1600 ;
      RECT 35.1000 14.8400 35.7800 265.1600 ;
      RECT 30.1300 14.8400 33.7800 265.1600 ;
      RECT 28.1300 14.8400 28.8100 265.1600 ;
      RECT 23.1600 14.8400 26.8100 265.1600 ;
      RECT 21.1600 14.8400 21.8400 265.1600 ;
      RECT 0.0000 14.8400 19.8400 265.1600 ;
      RECT 260.1400 14.6750 280.0000 265.1600 ;
      RECT 253.1700 14.6750 258.8200 14.8400 ;
      RECT 246.2000 14.6750 251.8500 14.8400 ;
      RECT 239.2300 14.6750 244.8800 14.8400 ;
      RECT 232.2600 14.6750 237.9100 14.8400 ;
      RECT 225.2900 14.6750 230.9400 14.8400 ;
      RECT 218.3200 14.6750 223.9700 14.8400 ;
      RECT 211.3500 14.6750 217.0000 14.8400 ;
      RECT 204.3800 14.6750 210.0300 14.8400 ;
      RECT 197.4100 14.6750 203.0600 14.8400 ;
      RECT 190.4400 14.6750 196.0900 14.8400 ;
      RECT 183.4700 14.6750 189.1200 14.8400 ;
      RECT 176.5000 14.6750 182.1500 14.8400 ;
      RECT 169.5300 14.6750 175.1800 14.8400 ;
      RECT 162.5600 14.6750 168.2100 14.8400 ;
      RECT 155.5900 14.6750 161.2400 14.8400 ;
      RECT 148.6200 14.6750 154.2700 14.8400 ;
      RECT 141.6500 14.6750 147.3000 14.8400 ;
      RECT 134.6800 14.6750 140.3300 14.8400 ;
      RECT 127.7100 14.6750 133.3600 14.8400 ;
      RECT 120.7400 14.6750 126.3900 14.8400 ;
      RECT 113.7700 14.6750 119.4200 14.8400 ;
      RECT 106.8000 14.6750 112.4500 14.8400 ;
      RECT 99.8300 14.6750 105.4800 14.8400 ;
      RECT 92.8600 14.6750 98.5100 14.8400 ;
      RECT 85.8900 14.6750 91.5400 14.8400 ;
      RECT 78.9200 14.6750 84.5700 14.8400 ;
      RECT 71.9500 14.6750 77.6000 14.8400 ;
      RECT 64.9800 14.6750 70.6300 14.8400 ;
      RECT 58.0100 14.6750 63.6600 14.8400 ;
      RECT 51.0400 14.6750 56.6900 14.8400 ;
      RECT 44.0700 14.6750 49.7200 14.8400 ;
      RECT 37.1000 14.6750 42.7500 14.8400 ;
      RECT 30.1300 14.6750 35.7800 14.8400 ;
      RECT 23.1600 14.6750 28.8100 14.8400 ;
      RECT 0.0000 14.6750 21.8400 14.8400 ;
      RECT 0.0000 0.6200 280.0000 14.6750 ;
      RECT 267.2500 0.0000 280.0000 0.6200 ;
      RECT 265.6500 0.0000 266.9500 0.6200 ;
      RECT 264.0500 0.0000 265.3500 0.6200 ;
      RECT 262.4500 0.0000 263.7500 0.6200 ;
      RECT 260.8500 0.0000 262.1500 0.6200 ;
      RECT 259.2500 0.0000 260.5500 0.6200 ;
      RECT 257.6500 0.0000 258.9500 0.6200 ;
      RECT 256.0500 0.0000 257.3500 0.6200 ;
      RECT 254.4500 0.0000 255.7500 0.6200 ;
      RECT 252.8500 0.0000 254.1500 0.6200 ;
      RECT 251.2500 0.0000 252.5500 0.6200 ;
      RECT 249.6500 0.0000 250.9500 0.6200 ;
      RECT 248.0500 0.0000 249.3500 0.6200 ;
      RECT 246.4500 0.0000 247.7500 0.6200 ;
      RECT 244.8500 0.0000 246.1500 0.6200 ;
      RECT 243.2500 0.0000 244.5500 0.6200 ;
      RECT 241.6500 0.0000 242.9500 0.6200 ;
      RECT 240.0500 0.0000 241.3500 0.6200 ;
      RECT 238.4500 0.0000 239.7500 0.6200 ;
      RECT 236.8500 0.0000 238.1500 0.6200 ;
      RECT 235.2500 0.0000 236.5500 0.6200 ;
      RECT 233.6500 0.0000 234.9500 0.6200 ;
      RECT 232.0500 0.0000 233.3500 0.6200 ;
      RECT 230.4500 0.0000 231.7500 0.6200 ;
      RECT 228.8500 0.0000 230.1500 0.6200 ;
      RECT 227.2500 0.0000 228.5500 0.6200 ;
      RECT 225.6500 0.0000 226.9500 0.6200 ;
      RECT 224.0500 0.0000 225.3500 0.6200 ;
      RECT 222.4500 0.0000 223.7500 0.6200 ;
      RECT 220.8500 0.0000 222.1500 0.6200 ;
      RECT 219.2500 0.0000 220.5500 0.6200 ;
      RECT 217.6500 0.0000 218.9500 0.6200 ;
      RECT 216.0500 0.0000 217.3500 0.6200 ;
      RECT 214.4500 0.0000 215.7500 0.6200 ;
      RECT 212.8500 0.0000 214.1500 0.6200 ;
      RECT 211.2500 0.0000 212.5500 0.6200 ;
      RECT 209.6500 0.0000 210.9500 0.6200 ;
      RECT 208.0500 0.0000 209.3500 0.6200 ;
      RECT 206.4500 0.0000 207.7500 0.6200 ;
      RECT 204.8500 0.0000 206.1500 0.6200 ;
      RECT 203.2500 0.0000 204.5500 0.6200 ;
      RECT 201.6500 0.0000 202.9500 0.6200 ;
      RECT 200.0500 0.0000 201.3500 0.6200 ;
      RECT 198.4500 0.0000 199.7500 0.6200 ;
      RECT 196.8500 0.0000 198.1500 0.6200 ;
      RECT 195.2500 0.0000 196.5500 0.6200 ;
      RECT 193.6500 0.0000 194.9500 0.6200 ;
      RECT 192.0500 0.0000 193.3500 0.6200 ;
      RECT 190.4500 0.0000 191.7500 0.6200 ;
      RECT 188.8500 0.0000 190.1500 0.6200 ;
      RECT 187.2500 0.0000 188.5500 0.6200 ;
      RECT 185.6500 0.0000 186.9500 0.6200 ;
      RECT 184.0500 0.0000 185.3500 0.6200 ;
      RECT 182.4500 0.0000 183.7500 0.6200 ;
      RECT 180.8500 0.0000 182.1500 0.6200 ;
      RECT 179.2500 0.0000 180.5500 0.6200 ;
      RECT 177.6500 0.0000 178.9500 0.6200 ;
      RECT 176.0500 0.0000 177.3500 0.6200 ;
      RECT 174.4500 0.0000 175.7500 0.6200 ;
      RECT 172.8500 0.0000 174.1500 0.6200 ;
      RECT 171.2500 0.0000 172.5500 0.6200 ;
      RECT 169.6500 0.0000 170.9500 0.6200 ;
      RECT 168.0500 0.0000 169.3500 0.6200 ;
      RECT 166.4500 0.0000 167.7500 0.6200 ;
      RECT 164.8500 0.0000 166.1500 0.6200 ;
      RECT 163.2500 0.0000 164.5500 0.6200 ;
      RECT 161.6500 0.0000 162.9500 0.6200 ;
      RECT 160.0500 0.0000 161.3500 0.6200 ;
      RECT 158.4500 0.0000 159.7500 0.6200 ;
      RECT 156.8500 0.0000 158.1500 0.6200 ;
      RECT 155.2500 0.0000 156.5500 0.6200 ;
      RECT 153.6500 0.0000 154.9500 0.6200 ;
      RECT 152.0500 0.0000 153.3500 0.6200 ;
      RECT 150.4500 0.0000 151.7500 0.6200 ;
      RECT 148.8500 0.0000 150.1500 0.6200 ;
      RECT 147.2500 0.0000 148.5500 0.6200 ;
      RECT 145.6500 0.0000 146.9500 0.6200 ;
      RECT 144.0500 0.0000 145.3500 0.6200 ;
      RECT 142.4500 0.0000 143.7500 0.6200 ;
      RECT 140.8500 0.0000 142.1500 0.6200 ;
      RECT 139.2500 0.0000 140.5500 0.6200 ;
      RECT 137.6500 0.0000 138.9500 0.6200 ;
      RECT 136.0500 0.0000 137.3500 0.6200 ;
      RECT 134.4500 0.0000 135.7500 0.6200 ;
      RECT 132.8500 0.0000 134.1500 0.6200 ;
      RECT 131.2500 0.0000 132.5500 0.6200 ;
      RECT 129.6500 0.0000 130.9500 0.6200 ;
      RECT 128.0500 0.0000 129.3500 0.6200 ;
      RECT 126.4500 0.0000 127.7500 0.6200 ;
      RECT 124.8500 0.0000 126.1500 0.6200 ;
      RECT 123.2500 0.0000 124.5500 0.6200 ;
      RECT 121.6500 0.0000 122.9500 0.6200 ;
      RECT 120.0500 0.0000 121.3500 0.6200 ;
      RECT 118.4500 0.0000 119.7500 0.6200 ;
      RECT 116.8500 0.0000 118.1500 0.6200 ;
      RECT 115.2500 0.0000 116.5500 0.6200 ;
      RECT 113.6500 0.0000 114.9500 0.6200 ;
      RECT 112.0500 0.0000 113.3500 0.6200 ;
      RECT 110.4500 0.0000 111.7500 0.6200 ;
      RECT 108.8500 0.0000 110.1500 0.6200 ;
      RECT 107.2500 0.0000 108.5500 0.6200 ;
      RECT 105.6500 0.0000 106.9500 0.6200 ;
      RECT 104.0500 0.0000 105.3500 0.6200 ;
      RECT 102.4500 0.0000 103.7500 0.6200 ;
      RECT 100.8500 0.0000 102.1500 0.6200 ;
      RECT 99.2500 0.0000 100.5500 0.6200 ;
      RECT 97.6500 0.0000 98.9500 0.6200 ;
      RECT 96.0500 0.0000 97.3500 0.6200 ;
      RECT 94.4500 0.0000 95.7500 0.6200 ;
      RECT 92.8500 0.0000 94.1500 0.6200 ;
      RECT 91.2500 0.0000 92.5500 0.6200 ;
      RECT 89.6500 0.0000 90.9500 0.6200 ;
      RECT 88.0500 0.0000 89.3500 0.6200 ;
      RECT 86.4500 0.0000 87.7500 0.6200 ;
      RECT 84.8500 0.0000 86.1500 0.6200 ;
      RECT 83.2500 0.0000 84.5500 0.6200 ;
      RECT 81.6500 0.0000 82.9500 0.6200 ;
      RECT 80.0500 0.0000 81.3500 0.6200 ;
      RECT 78.4500 0.0000 79.7500 0.6200 ;
      RECT 76.8500 0.0000 78.1500 0.6200 ;
      RECT 75.2500 0.0000 76.5500 0.6200 ;
      RECT 73.6500 0.0000 74.9500 0.6200 ;
      RECT 72.0500 0.0000 73.3500 0.6200 ;
      RECT 70.4500 0.0000 71.7500 0.6200 ;
      RECT 68.8500 0.0000 70.1500 0.6200 ;
      RECT 67.2500 0.0000 68.5500 0.6200 ;
      RECT 65.6500 0.0000 66.9500 0.6200 ;
      RECT 64.0500 0.0000 65.3500 0.6200 ;
      RECT 62.4500 0.0000 63.7500 0.6200 ;
      RECT 60.8500 0.0000 62.1500 0.6200 ;
      RECT 59.2500 0.0000 60.5500 0.6200 ;
      RECT 57.6500 0.0000 58.9500 0.6200 ;
      RECT 56.0500 0.0000 57.3500 0.6200 ;
      RECT 54.4500 0.0000 55.7500 0.6200 ;
      RECT 52.8500 0.0000 54.1500 0.6200 ;
      RECT 51.2500 0.0000 52.5500 0.6200 ;
      RECT 49.6500 0.0000 50.9500 0.6200 ;
      RECT 48.0500 0.0000 49.3500 0.6200 ;
      RECT 46.4500 0.0000 47.7500 0.6200 ;
      RECT 44.8500 0.0000 46.1500 0.6200 ;
      RECT 43.2500 0.0000 44.5500 0.6200 ;
      RECT 41.6500 0.0000 42.9500 0.6200 ;
      RECT 40.0500 0.0000 41.3500 0.6200 ;
      RECT 38.4500 0.0000 39.7500 0.6200 ;
      RECT 36.8500 0.0000 38.1500 0.6200 ;
      RECT 35.2500 0.0000 36.5500 0.6200 ;
      RECT 33.6500 0.0000 34.9500 0.6200 ;
      RECT 32.0500 0.0000 33.3500 0.6200 ;
      RECT 30.4500 0.0000 31.7500 0.6200 ;
      RECT 28.8500 0.0000 30.1500 0.6200 ;
      RECT 27.2500 0.0000 28.5500 0.6200 ;
      RECT 25.6500 0.0000 26.9500 0.6200 ;
      RECT 24.0500 0.0000 25.3500 0.6200 ;
      RECT 22.4500 0.0000 23.7500 0.6200 ;
      RECT 20.8500 0.0000 22.1500 0.6200 ;
      RECT 19.2500 0.0000 20.5500 0.6200 ;
      RECT 17.6500 0.0000 18.9500 0.6200 ;
      RECT 16.0500 0.0000 17.3500 0.6200 ;
      RECT 14.4500 0.0000 15.7500 0.6200 ;
      RECT 12.8500 0.0000 14.1500 0.6200 ;
      RECT 0.0000 0.0000 12.5500 0.6200 ;
  END
END sram_w16_out

END LIBRARY
